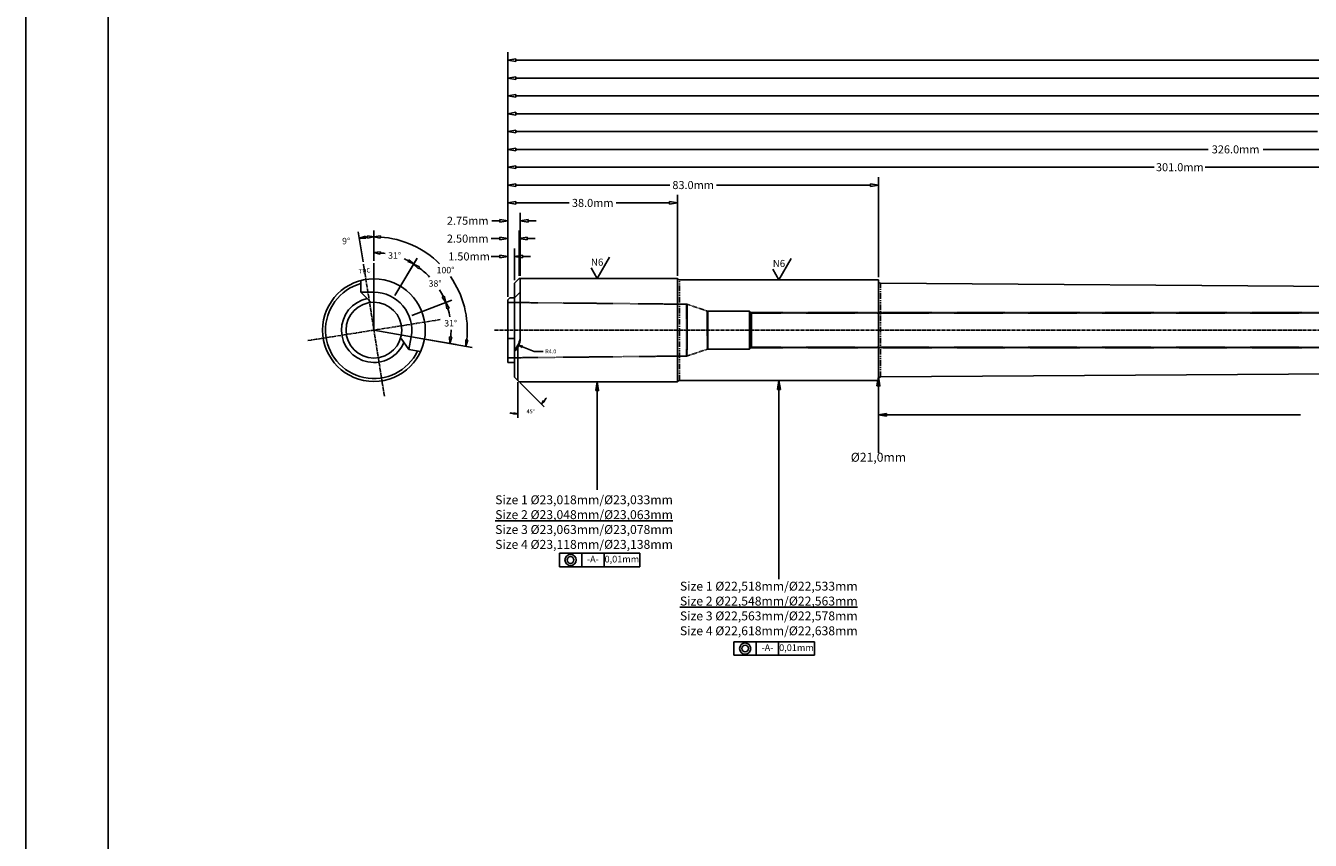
# Model space of a CAD drawing. Units: inches. Extents: x 0 to 841, y 0 to 594.
# Drawn here: x 0 to 288, y 183 to 365 of the extents above; entities that cross this region are included whole.
import ezdxf
from ezdxf.enums import TextEntityAlignment as Align

# ---------------------------------------------------------------- set-up
doc = ezdxf.new("R2010")
doc.units = ezdxf.units.IN
doc.header["$MEASUREMENT"] = 0
for name, pattern in [('CENTER2', [1.125, 0.75, -0.125, 0.125, -0.125]), ('HIDDEN2', [0.1875, 0.125, -0.0625]), ('PHANTOM', [2.5, 1.25, -0.25, 0.25, -0.25, 0.25, -0.25])]:
    doc.linetypes.add(name, pattern=pattern)
for name, color, linetype in [('CENTER', 1, 'CENTER2'), ('CENTERLINE', 1, 'CENTER2'), ('HIDDEN', 5, 'HIDDEN2'), ('PHANTOM', 252, 'PHANTOM'), ('TEXT', 5, 'Continuous')]:
    doc.layers.add(name, color=color, linetype=linetype)
doc.dimstyles.get("Standard").update_dxf_attribs({"dimtxt": 0.18, "dimasz": 0.18, "dimexe": 0.18, "dimexo": 0.0625, "dimgap": 0.09, "dimtad": 0, "dimtih": 1, "dimtoh": 1, "dimdec": 4, "dimzin": 0, "dimdsep": 46, "dimtxsty": 'Standard', "dimcen": 0.09, "dimadec": 0, "dimazin": 0, "dimtfac": 1, "dimtdec": 4, "dimtofl": 0, "dimtmove": 0, "dimatfit": 3, "dimfxl": 0, "dimtolj": 1, "dimtzin": 0, "dimarcsym": 0})
doc.dimstyles.new('Standard$0', dxfattribs={"dimscale": 10, "dimtxt": 0.18, "dimasz": 0.18, "dimexe": 0.18, "dimexo": 0.0625, "dimgap": 0.09, "dimtad": 0, "dimtih": 1, "dimtoh": 1, "dimdec": 4, "dimzin": 4, "dimdsep": 46, "dimtxsty": 'Standard', "dimblk": 'CLOSEDBLANK', "dimcen": 0.09, "dimadec": 5, "dimazin": 1, "dimtfac": 1, "dimtdec": 4, "dimtofl": 0, "dimtmove": 0, "dimatfit": 3, "dimldrblk": 'CLOSEDBLANK', "dimfxl": 0, "dimtolj": 1, "dimtzin": 0, "dimarcsym": 0})

# ---------------------------------------------------------------- blocks, each defined once
blk = doc.blocks.new('_ClosedBlank')
at = {"color": 0, "linetype": 'ByBlock', "lineweight": -2}
for p, q in [((-1, 0.17), (0, 0)), ((-1, 0.17), (-1, -0.17)), ((0, 0), (-1, -0.17))]:
    blk.add_line(p, q, dxfattribs=at)
blk = doc.blocks.new('*D17')
at = {"color": 0, "lineweight": -2}
for p, q in [((108, 304.44), (108, 315.32)), ((109.5, 308.19), (109.5, 315.32)), ((106.2, 313.52), (104.25, 313.52)), ((111.3, 313.52), (113.1, 313.52))]:
    blk.add_line(p, q, dxfattribs=at)
at = {"layer": 'Defpoints', "color": 0}
for p in [(109.5, 313.52), (109.5, 307.56), (108, 303.81)]:
    blk.add_point(p, dxfattribs=at)
at = {"color": 0, "lineweight": -2, "xscale": 1.8, "yscale": 1.8, "zscale": 1.8}
blk.add_blockref('_ClosedBlank', (108, 313.52), dxfattribs=at)
at = {"color": 0, "lineweight": -2, "xscale": 1.8, "yscale": 1.8, "zscale": 1.8, "rotation": 180}
blk.add_blockref('_ClosedBlank', (109.5, 313.52), dxfattribs=at)
at = {"color": 0, "insert": (99.3, 313.52), "char_height": 1.8, "attachment_point": 5}
blk.add_mtext('\\A1;1.50mm', dxfattribs=at)
blk = doc.blocks.new('*D18')
at = {"color": 0, "lineweight": -2}
for p, q in [((108, 304.44), (108, 327.32)), ((109.8, 325.52), (121.75, 325.52)), ((144.2, 325.52), (132.25, 325.52)), ((146, 309.19), (146, 327.32))]:
    blk.add_line(p, q, dxfattribs=at)
at = {"layer": 'Defpoints', "color": 0}
for p in [(146, 325.52), (146, 308.56), (108, 303.81)]:
    blk.add_point(p, dxfattribs=at)
at = {"color": 0, "lineweight": -2, "xscale": 1.8, "yscale": 1.8, "zscale": 1.8, "rotation": 180}
blk.add_blockref('_ClosedBlank', (108, 325.52), dxfattribs=at)
at = {"color": 0, "lineweight": -2, "xscale": 1.8, "yscale": 1.8, "zscale": 1.8}
blk.add_blockref('_ClosedBlank', (146, 325.52), dxfattribs=at)
at = {"color": 0, "insert": (127, 325.52), "char_height": 1.8, "attachment_point": 5}
blk.add_mtext('\\A1;38.0mm', dxfattribs=at)
blk = doc.blocks.new('*D19')
at = {"color": 0, "lineweight": -2}
for p, q in [((108, 304.44), (108, 331.32)), ((191, 308.9), (191, 331.32)), ((109.8, 329.52), (144.25, 329.52)), ((189.2, 329.52), (154.75, 329.52))]:
    blk.add_line(p, q, dxfattribs=at)
at = {"layer": 'Defpoints', "color": 0}
for p in [(108, 329.52), (191, 308.27), (108, 303.81)]:
    blk.add_point(p, dxfattribs=at)
at = {"color": 0, "lineweight": -2, "xscale": 1.8, "yscale": 1.8, "zscale": 1.8, "rotation": 180}
blk.add_blockref('_ClosedBlank', (108, 329.52), dxfattribs=at)
at = {"color": 0, "lineweight": -2, "xscale": 1.8, "yscale": 1.8, "zscale": 1.8}
blk.add_blockref('_ClosedBlank', (191, 329.52), dxfattribs=at)
at = {"color": 0, "insert": (149.5, 329.52), "char_height": 1.8, "attachment_point": 5}
blk.add_mtext('\\A1;83.0mm', dxfattribs=at)
blk = doc.blocks.new('*D20')
at = {"color": 0, "lineweight": -2}
for p, q in [((108, 304.44), (108, 335.32)), ((409, 306.62), (409, 335.32)), ((109.8, 333.52), (252.8, 333.52)), ((407.2, 333.52), (264.2, 333.52))]:
    blk.add_line(p, q, dxfattribs=at)
at = {"layer": 'Defpoints', "color": 0}
for p in [(108, 333.52), (409, 306), (108, 303.81)]:
    blk.add_point(p, dxfattribs=at)
at = {"color": 0, "lineweight": -2, "xscale": 1.8, "yscale": 1.8, "zscale": 1.8, "rotation": 180}
blk.add_blockref('_ClosedBlank', (108, 333.52), dxfattribs=at)
at = {"color": 0, "lineweight": -2, "xscale": 1.8, "yscale": 1.8, "zscale": 1.8}
blk.add_blockref('_ClosedBlank', (409, 333.52), dxfattribs=at)
at = {"color": 0, "insert": (258.5, 333.52), "char_height": 1.8, "attachment_point": 5}
blk.add_mtext('\\A1;301.0mm', dxfattribs=at)
blk = doc.blocks.new('*D21')
at = {"color": 0, "lineweight": -2}
for p, q in [((108, 304.44), (108, 339.32)), ((109.8, 337.52), (264.85, 337.52)), ((432.2, 337.52), (277.15, 337.52)), ((434, 306.11), (434, 339.32))]:
    blk.add_line(p, q, dxfattribs=at)
at = {"layer": 'Defpoints', "color": 0}
for p in [(108, 337.52), (434, 305.49), (108, 303.81)]:
    blk.add_point(p, dxfattribs=at)
at = {"color": 0, "lineweight": -2, "xscale": 1.8, "yscale": 1.8, "zscale": 1.8, "rotation": 180}
blk.add_blockref('_ClosedBlank', (108, 337.52), dxfattribs=at)
at = {"color": 0, "lineweight": -2, "xscale": 1.8, "yscale": 1.8, "zscale": 1.8}
blk.add_blockref('_ClosedBlank', (434, 337.52), dxfattribs=at)
at = {"color": 0, "insert": (271, 337.52), "char_height": 1.8, "attachment_point": 5}
blk.add_mtext('\\A1;326.0mm', dxfattribs=at)
blk = doc.blocks.new('*D22')
at = {"color": 0, "lineweight": -2}
for p, q in [((108, 304.44), (108, 343.32)), ((483, 306.02), (483, 343.32)), ((109.8, 341.52), (289.35, 341.52)), ((481.2, 341.52), (301.65, 341.52))]:
    blk.add_line(p, q, dxfattribs=at)
at = {"layer": 'Defpoints', "color": 0}
for p in [(483, 341.52), (483, 305.4), (108, 303.81)]:
    blk.add_point(p, dxfattribs=at)
at = {"color": 0, "lineweight": -2, "xscale": 1.8, "yscale": 1.8, "zscale": 1.8, "rotation": 180}
blk.add_blockref('_ClosedBlank', (108, 341.52), dxfattribs=at)
at = {"color": 0, "lineweight": -2, "xscale": 1.8, "yscale": 1.8, "zscale": 1.8}
blk.add_blockref('_ClosedBlank', (483, 341.52), dxfattribs=at)
at = {"color": 0, "insert": (295.5, 341.52), "char_height": 1.8, "attachment_point": 5}
blk.add_mtext('\\A1;375.0mm', dxfattribs=at)
blk = doc.blocks.new('*D23')
at = {"color": 0, "lineweight": -2}
for p, q in [((108, 304.44), (108, 347.32)), ((109.8, 345.52), (309.15, 345.52)), ((520.2, 345.52), (320.85, 345.52)), ((522, 305.4), (522, 347.32))]:
    blk.add_line(p, q, dxfattribs=at)
at = {"layer": 'Defpoints', "color": 0}
for p in [(522, 345.52), (108, 303.81), (522, 304.77)]:
    blk.add_point(p, dxfattribs=at)
at = {"color": 0, "lineweight": -2, "xscale": 1.8, "yscale": 1.8, "zscale": 1.8, "rotation": 180}
blk.add_blockref('_ClosedBlank', (108, 345.52), dxfattribs=at)
at = {"color": 0, "lineweight": -2, "xscale": 1.8, "yscale": 1.8, "zscale": 1.8}
blk.add_blockref('_ClosedBlank', (522, 345.52), dxfattribs=at)
at = {"color": 0, "insert": (315, 345.52), "char_height": 1.8, "attachment_point": 5}
blk.add_mtext('\\A1;414.0mm', dxfattribs=at)
blk = doc.blocks.new('*D24')
at = {"color": 0, "lineweight": -2}
for p, q in [((108, 304.44), (108, 351.31)), ((656, 305.25), (656, 351.31)), ((109.8, 349.51), (375.85, 349.51)), ((654.2, 349.51), (388.15, 349.51))]:
    blk.add_line(p, q, dxfattribs=at)
at = {"layer": 'Defpoints', "color": 0}
for p in [(656, 349.51), (108, 303.81), (656, 304.62)]:
    blk.add_point(p, dxfattribs=at)
at = {"color": 0, "lineweight": -2, "xscale": 1.8, "yscale": 1.8, "zscale": 1.8, "rotation": 180}
blk.add_blockref('_ClosedBlank', (108, 349.51), dxfattribs=at)
at = {"color": 0, "lineweight": -2, "xscale": 1.8, "yscale": 1.8, "zscale": 1.8}
blk.add_blockref('_ClosedBlank', (656, 349.51), dxfattribs=at)
at = {"color": 0, "insert": (382, 349.51), "char_height": 1.8, "attachment_point": 5}
blk.add_mtext('\\A1;548.0mm', dxfattribs=at)
blk = doc.blocks.new('*D25')
at = {"color": 0, "lineweight": -2}
for p, q in [((108, 304.44), (108, 355.31)), ((692, 305), (692, 355.31)), ((109.8, 353.51), (393.85, 353.51)), ((690.2, 353.51), (406.15, 353.51))]:
    blk.add_line(p, q, dxfattribs=at)
at = {"layer": 'Defpoints', "color": 0}
for p in [(692, 353.51), (108, 303.81), (692, 304.37)]:
    blk.add_point(p, dxfattribs=at)
at = {"color": 0, "lineweight": -2, "xscale": 1.8, "yscale": 1.8, "zscale": 1.8, "rotation": 180}
blk.add_blockref('_ClosedBlank', (108, 353.51), dxfattribs=at)
at = {"color": 0, "lineweight": -2, "xscale": 1.8, "yscale": 1.8, "zscale": 1.8}
blk.add_blockref('_ClosedBlank', (692, 353.51), dxfattribs=at)
at = {"color": 0, "insert": (400, 353.51), "char_height": 1.8, "attachment_point": 5}
blk.add_mtext('\\A1;584.0mm', dxfattribs=at)
blk = doc.blocks.new('*D26')
at = {"color": 0, "lineweight": -2}
for p, q in [((106.2, 317.52), (104.25, 317.52)), ((108, 304.44), (108, 319.32)), ((110.5, 309.19), (110.5, 319.32)), ((112.3, 317.52), (114.1, 317.52))]:
    blk.add_line(p, q, dxfattribs=at)
at = {"layer": 'Defpoints', "color": 0}
for p in [(110.5, 317.52), (110.5, 308.56), (108, 303.81)]:
    blk.add_point(p, dxfattribs=at)
at = {"color": 0, "lineweight": -2, "xscale": 1.8, "yscale": 1.8, "zscale": 1.8}
blk.add_blockref('_ClosedBlank', (108, 317.52), dxfattribs=at)
at = {"color": 0, "lineweight": -2, "xscale": 1.8, "yscale": 1.8, "zscale": 1.8, "rotation": 180}
blk.add_blockref('_ClosedBlank', (110.5, 317.52), dxfattribs=at)
at = {"color": 0, "insert": (99, 317.52), "char_height": 1.8, "attachment_point": 5}
blk.add_mtext('\\A1;2.50mm', dxfattribs=at)
blk = doc.blocks.new('*D27')
at = {"color": 0, "lineweight": -2}
for p, q in [((108, 308.87), (108, 323.32)), ((110.75, 309.19), (110.75, 323.32)), ((106.2, 321.52), (104.4, 321.52)), ((112.55, 321.52), (114.35, 321.52))]:
    blk.add_line(p, q, dxfattribs=at)
at = {"layer": 'Defpoints', "color": 0}
for p in [(110.75, 321.52), (108, 308.25), (110.75, 308.56)]:
    blk.add_point(p, dxfattribs=at)
at = {"color": 0, "lineweight": -2, "xscale": 1.8, "yscale": 1.8, "zscale": 1.8}
blk.add_blockref('_ClosedBlank', (108, 321.52), dxfattribs=at)
at = {"color": 0, "lineweight": -2, "xscale": 1.8, "yscale": 1.8, "zscale": 1.8, "rotation": 180}
blk.add_blockref('_ClosedBlank', (110.75, 321.52), dxfattribs=at)
at = {"color": 0, "insert": (99, 321.52), "char_height": 1.8, "attachment_point": 5}
blk.add_mtext('\\A1;2.75mm', dxfattribs=at)
blk = doc.blocks.new('*D28')
at = {"color": 0, "lineweight": -2}
for p, q in [((108, 304.44), (108, 359.31)), ((109.8, 357.51), (414.35, 357.51)), ((731.2, 357.51), (426.65, 357.51)), ((733, 304.92), (733, 359.31))]:
    blk.add_line(p, q, dxfattribs=at)
at = {"layer": 'Defpoints', "color": 0}
for p in [(733, 357.51), (108, 303.81), (733, 304.3)]:
    blk.add_point(p, dxfattribs=at)
at = {"color": 0, "lineweight": -2, "xscale": 1.8, "yscale": 1.8, "zscale": 1.8, "rotation": 180}
blk.add_blockref('_ClosedBlank', (108, 357.51), dxfattribs=at)
at = {"color": 0, "lineweight": -2, "xscale": 1.8, "yscale": 1.8, "zscale": 1.8}
blk.add_blockref('_ClosedBlank', (733, 357.51), dxfattribs=at)
at = {"color": 0, "insert": (420.5, 357.51), "char_height": 1.8, "attachment_point": 5}
blk.add_mtext('\\A1;625.0mm', dxfattribs=at)
blk = doc.blocks.new('*D44')
at = {"color": 0, "lineweight": -2}
for p, q in [((110.25, 285.37), (110.25, 277.34)), ((110.72, 285.21), (116.16, 279.78))]:
    blk.add_line(p, q, dxfattribs=at)
for start, end in [(321.9261, 328.8523), (256.1477, 263.0739)]:
    blk.add_arc((110.25, 285.68), 7.45, start, end, dxfattribs=at)
at = {"layer": 'Defpoints', "color": 0}
for p in [(110.25, 293.73), (109.5, 286.44), (110.25, 285.68), (110.5, 285.43), (112.18, 278.49)]:
    blk.add_point(p, dxfattribs=at)
at = {"color": 0, "lineweight": -2, "xscale": 0.8999999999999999, "yscale": 0.8999999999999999, "zscale": 0.8999999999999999}
for p, rotation in [((115.52, 280.42), 228.4630740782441), ((110.25, 278.24), 356.5369259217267)]:
    blk.add_blockref('_ClosedBlank', p, dxfattribs=dict(at, rotation=rotation))
at = {"color": 0, "insert": (113.1, 278.8), "char_height": 0.9, "attachment_point": 5}
blk.add_mtext('\\A1;45°', dxfattribs=at)
blk = doc.blocks.new('*D15')
at = {"color": 0, "lineweight": -2}
for p, q in [((78, 312.5), (78, 315.81)), ((82.67, 304.77), (87.69, 313.12))]:
    blk.add_line(p, q, dxfattribs=at)
for start, end in [(81.7869, 85.2476), (63.7524, 66.9446)]:
    blk.add_arc((78, 297), 17.37, start, end, dxfattribs=at)
at = {"layer": 'Defpoints', "color": 0}
for p in [(78, 312), (84.13, 313.25), (82.41, 304.34), (78, 297), (78, 297)]:
    blk.add_point(p, dxfattribs=at)
at = {"color": 0, "lineweight": -2, "xscale": 1.44, "yscale": 1.44, "zscale": 1.44}
for p, rotation in [((78, 314.37), 177.6237779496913), ((86.94, 311.89), 331.3762212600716)]:
    blk.add_blockref('_ClosedBlank', p, dxfattribs=dict(at, rotation=rotation))
at = {"color": 0, "insert": (82.64, 313.73), "char_height": 1.44, "attachment_point": 5}
blk.add_mtext('\\A1;31°', dxfattribs=at)
blk = doc.blocks.new('*D16')
at = {"color": 0, "lineweight": -2}
for p, q in [((82.67, 304.77), (87.62, 313.01)), ((86.46, 300.25), (95.44, 303.69))]:
    blk.add_line(p, q, dxfattribs=at)
for start, end in [(43.6521, 54.2118), (25.7882, 31.5463)]:
    blk.add_arc((78, 297), 17.24, start, end, dxfattribs=at)
at = {"layer": 'Defpoints', "color": 0}
for p in [(89.9, 309.47), (82.41, 304.34), (86, 300.07), (78, 297), (78, 297)]:
    blk.add_point(p, dxfattribs=at)
at = {"color": 0, "lineweight": -2, "xscale": 1.44, "yscale": 1.44, "zscale": 1.44}
for p, rotation in [((86.88, 311.77), 146.6059045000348), ((94.09, 303.18), 293.3940946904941)]:
    blk.add_blockref('_ClosedBlank', p, dxfattribs=dict(at, rotation=rotation))
at = {"color": 0, "insert": (91.7, 307.46), "char_height": 1.44, "attachment_point": 5}
blk.add_mtext('\\A1;38°', dxfattribs=at)
blk = doc.blocks.new('*D40')
at = {"color": 0, "lineweight": -2}
for p, q in [((78, 312.5), (78, 319.36)), ((89.82, 294.92), (100.02, 293.12))]:
    blk.add_line(p, q, dxfattribs=at)
for start, end in [(45.3657, 86.0562), (353.9438, 35.0275)]:
    blk.add_arc((78, 297), 20.92, start, end, dxfattribs=at)
at = {"layer": 'Defpoints', "color": 0}
for p in [(78, 312), (97.21, 305.29), (78, 297), (78, 297), (89.33, 295)]:
    blk.add_point(p, dxfattribs=at)
at = {"color": 0, "lineweight": -2, "xscale": 1.44, "yscale": 1.44, "zscale": 1.44}
for p, rotation in [((78, 317.92), 178.028112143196), ((98.61, 293.37), 261.971886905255)]:
    blk.add_blockref('_ClosedBlank', p, dxfattribs=dict(at, rotation=rotation))
at = {"color": 0, "insert": (94.03, 310.45), "char_height": 1.44, "attachment_point": 5}
blk.add_mtext('\\A1;100°', dxfattribs=at)
blk = doc.blocks.new('*D41')
at = {"color": 0, "lineweight": -2}
for p, q in [((86.46, 300.25), (95.47, 303.71)), ((89.82, 294.92), (96.43, 293.75))]:
    blk.add_line(p, q, dxfattribs=at)
for start, end in [(9.9283, 16.2222), (354.7778, 0.3259)]:
    blk.add_arc((78, 297), 17.27, start, end, dxfattribs=at)
at = {"layer": 'Defpoints', "color": 0}
for p in [(86, 300.07), (94.98, 300.2), (78, 297), (78, 297), (89.33, 295)]:
    blk.add_point(p, dxfattribs=at)
at = {"color": 0, "lineweight": -2, "xscale": 1.44, "yscale": 1.44, "zscale": 1.44}
for p, rotation in [((94.13, 303.19), 108.6110943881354), ((95.01, 294), 262.3889047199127)]:
    blk.add_blockref('_ClosedBlank', p, dxfattribs=dict(at, rotation=rotation))
at = {"color": 0, "insert": (95.2, 298.54), "char_height": 1.44, "attachment_point": 5}
blk.add_mtext('\\A1;31°', dxfattribs=at)
blk = doc.blocks.new('*D42')
at = {"color": 0, "lineweight": -2}
for p, q in [((75.58, 312.31), (74.5, 319.07)), ((78, 312.5), (78, 319.35))]:
    blk.add_line(p, q, dxfattribs=at)
blk.add_arc((78, 297), 20.91, 93.9466, 95.0534, dxfattribs=at)
at = {"layer": 'Defpoints', "color": 0}
for p in [(76.91, 317.88), (75.65, 311.82), (78, 312), (78, 297), (80.35, 282.18)]:
    blk.add_point(p, dxfattribs=at)
at = {"color": 0, "lineweight": -2, "xscale": 1.44, "yscale": 1.44, "zscale": 1.44}
for p, rotation in [((74.73, 317.65), 187.0267074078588), ((78, 317.91), 1.973292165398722)]:
    blk.add_blockref('_ClosedBlank', p, dxfattribs=dict(at, rotation=rotation))
at = {"color": 0, "insert": (71.78, 316.96), "char_height": 1.44, "attachment_point": 5}
blk.add_mtext('\\A1;9°', dxfattribs=at)
blk = doc.blocks.new('*D43')
at = {"color": 0, "lineweight": -2}
for p, q in [((113.86, 292.23), (111.29, 293.27)), ((115.89, 292.23), (113.86, 292.23))]:
    blk.add_line(p, q, dxfattribs=at)
at = {"layer": 'Defpoints', "color": 0}
for p in [(106.75, 295.11), (110.46, 293.61)]:
    blk.add_point(p, dxfattribs=at)
at = {"color": 0, "lineweight": -2, "xscale": 0.8999999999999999, "yscale": 0.8999999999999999, "zscale": 0.8999999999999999, "rotation": 157.9266221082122}
blk.add_blockref('_ClosedBlank', (110.46, 293.61), dxfattribs=at)
at = {"color": 0, "insert": (117.61, 292.23), "char_height": 0.9, "attachment_point": 5}
blk.add_mtext('\\A1;R4.0', dxfattribs=at)

msp = doc.modelspace()

# ---------------------------------------------------------------- linework, layer by layer
at = {"color": 1}
for q in [(77.99996, 312), (92.77208, 294.39527)]:
    msp.add_line((77.99996, 297), q, dxfattribs=at)
for p, q in [((126.62682, 310.94625), (128.00164, 308.565)), ((128.00164, 308.565), (130.75127, 313.3275)), ((168.72684, 308.275), (171.47648, 313.0375)), ((75.09521, 305.4824), (75.09521, 308.1271)), ((109.49996, 307.56164), (110.50332, 308.565)), ((110.50332, 308.565), (145.99996, 308.565)), ((110.74996, 295.11191), (110.74996, 308.565)), ((145.99996, 285.435), (145.99996, 308.565)), ((146.45373, 308.275), (190.99996, 308.275)), ((167.35203, 310.65625), (168.72684, 308.275)), ((190.99996, 285.725), (190.99996, 308.275)), ((77.21026, 303.36735), (75.09521, 305.4824)), ((77.99996, 305.4824), (75.09521, 305.4824)), ((109.49996, 304.25), (109.49996, 307.56164)), ((109.49996, 304.2324), (110.74996, 305.4824)), ((191.49652, 307.49658), (408.99996, 306)), ((77.21026, 303.36735), (77.19545, 303.198)), ((107.99996, 303.815), (108.43496, 304.25)), ((107.99996, 289.75), (107.99996, 303.815)), ((107.99996, 303.20498), (109.49996, 303.19002)), ((108.43496, 304.25), (109.49996, 304.25)), ((109.49996, 294.66584), (109.49996, 304.86363)), ((83.9641, 295.13143), (84.13345, 295.11661)), ((84.13345, 295.11661), (85.84909, 292.66642)), ((85.84909, 292.66642), (86.3535, 295.52704)), ((107.99996, 295.12402), (109.49996, 295.12402)), ((109.24996, 295.12402), (109.49996, 295.12402)), ((109.49996, 286.43835), (109.49996, 294.66584)), ((110.25332, 293.72903), (110.25332, 285.685)), ((85.84909, 292.66642), (88.45362, 292.20717)), ((107.99996, 289.75), (109.49996, 289.75)), ((191.49996, 286.50344), (408.99996, 288)), ((109.49996, 286.43835), (110.50332, 285.435)), ((110.50332, 285.435), (145.99996, 285.435)), ((146.45373, 285.725), (190.99332, 285.725)), ((190.99996, 278), (285.57106, 278)), ((119.54128, 243.96997), (119.54128, 246.96997))]:
    msp.add_line(p, q)
for points in [[(-0.00004, 0), (840.99996, 0), (840.99996, 594), (-0.00004, 594)], [(18.49996, 20), (822.49996, 20), (822.49996, 574), (18.49996, 574)]]:
    msp.add_lwpolyline(points, close=True)
for radius in [11.5, 6.25]:
    msp.add_circle((77.99996, 297), radius)
for centre, radius, start, end in [((146.45373, 308.775), 0.5, 204.8345875, 270), ((191.49996, 307.99657), 0.5, 180, 270), ((77.99996, 297), 10.85, 105.5285723, 334.4714272), ((77.99996, 297), 8.4824, 349.9999996, 89.9999999), ((77.99996, 297), 7.25, 102.0437004, 337.9562974), ((106.74996, 295.57116), 4, 313.4325366, 0), ((106.74996, 295.11191), 4, 313.4325366, 0), ((146.45373, 285.225), 0.5, 90, 155.1654125), ((191.49996, 286.00342), 0.5, 90, 180)]:
    msp.add_arc(centre, radius, start, end)
at = {"layer": 'CENTER'}
msp.add_line((80.34648, 282.18467), (75.65345, 311.81532), dxfattribs=at)
at = {"layer": 'CENTERLINE'}
for p, q in [((92.81529, 299.34651), (63.18464, 294.65348)), ((104.99996, 297), (735.99996, 297))]:
    msp.add_line(p, q, dxfattribs=at)
at = {"layer": 'HIDDEN'}
for p, q in [((109.49996, 303.19002), (148.02475, 302.80578)), ((148.02466, 291.19421), (148.02466, 302.80578)), ((148.17841, 291.22005), (148.17841, 302.77997)), ((148.17841, 302.77997), (152.62634, 301.29088)), ((152.62634, 292.70913), (152.62634, 301.29088)), ((152.78507, 292.735), (152.78507, 301.265)), ((152.78514, 301.265), (162.12332, 301.265)), ((162.12332, 292.735), (162.12332, 301.265)), ((162.12332, 301.265), (162.57832, 300.81)), ((162.42592, 300.9624), (732.99996, 300.9624)), ((162.42592, 293.0376), (162.42592, 300.9624)), ((162.57832, 300.81), (732.99996, 300.81)), ((162.57832, 293.19), (162.57832, 300.81)), ((107.99996, 290.79501), (148.02466, 291.19421)), ((148.17841, 291.22005), (152.62634, 292.70913)), ((152.78507, 292.735), (162.12332, 292.735)), ((162.12332, 292.735), (162.61335, 293.22503)), ((162.42592, 293.0376), (732.99996, 293.0376)), ((162.57832, 293.19), (732.99996, 293.19))]:
    msp.add_line(p, q, dxfattribs=at)
for centre, start, end in [((148.01977, 302.3058), 71.5017102, 89.428565), ((152.78514, 301.765), 251.4904, 270), ((148.01967, 291.69419), 270.571435, 288.50951), ((152.78507, 292.235), 90, 108.50951)]:
    msp.add_arc(centre, 0.5, start, end, dxfattribs=at)
at = {"layer": 'PHANTOM'}
for p, q in [((146.45373, 285.725), (146.45373, 308.275)), ((191.49996, 286.50342), (191.49996, 307.49657))]:
    msp.add_line(p, q, dxfattribs=at)
at = {"layer": 'TEXT', "color": 7}
for p, q in [((119.54128, 246.96997), (124.54128, 246.96997)), ((124.54128, 246.96997), (129.54128, 246.96997)), ((124.54128, 243.96997), (124.54128, 246.96997)), ((129.54128, 246.96997), (137.54128, 246.96997)), ((129.54128, 243.96997), (129.54128, 246.96997)), ((137.54128, 243.96997), (137.54128, 246.96997)), ((119.54128, 243.96997), (124.54128, 243.96997)), ((124.54128, 243.96997), (129.54128, 243.96997)), ((129.54128, 243.96997), (137.54128, 243.96997)), ((158.6478, 224.11717), (158.6478, 227.11717)), ((158.6478, 227.11717), (163.6478, 227.11717)), ((163.6478, 227.11717), (168.6478, 227.11717)), ((163.6478, 224.11717), (163.6478, 227.11717)), ((168.6478, 227.11717), (176.6478, 227.11717)), ((168.6478, 224.11717), (168.6478, 227.11717)), ((176.6478, 224.11717), (176.6478, 227.11717)), ((158.6478, 224.11717), (163.6478, 224.11717)), ((163.6478, 224.11717), (168.6478, 224.11717)), ((168.6478, 224.11717), (176.6478, 224.11717))]:
    msp.add_line(p, q, dxfattribs=at)
for centre, radius in [((122.04128, 245.46997), 1.25), ((122.04128, 245.46997), 0.75), ((161.1478, 225.61717), 1.25), ((161.1478, 225.61717), 0.75)]:
    msp.add_circle(centre, radius, dxfattribs=at)

# ---------------------------------------------------------------- block references
at = {"xscale": -1.799999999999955, "yscale": 1.800000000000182, "zscale": 1.8}
msp.add_blockref('_ClosedBlank', (190.99996, 278), dxfattribs=at)

# ---------------------------------------------------------------- texts
for p in [(128.00164, 310.94625), (168.72684, 310.65625)]:
    msp.add_text('N6', height=1.5875).set_placement(p, align=Align.BOTTOM_CENTER)
at = {"insert": (75.91953, 310.13533), "char_height": 1, "width": 2.2352304, "attachment_point": 5, "rotation": 9}
msp.add_mtext('TDC', dxfattribs=at)
at = {"insert": (190.99996, 269.5), "char_height": 2, "width": 10.5482646, "attachment_point": 2}
msp.add_mtext('\\A1;%%C21,0mm', dxfattribs=at)
at = {"layer": 'TEXT', "color": 7}
for s, insert, char_height, width, attachment_point in [('\\A1;Size 1 %%C23,018mm/%%C23,033mm\\P{\\LSize 2 %%C23,048mm/%%C23,063mm}\\PSize 3 %%C23,063mm/%%C23,078mm\\PSize 4 %%C23,118mm/%%C23,138mm', (105.15622, 259.96997), 2, 48.5376086, 1), ('-A-', (127.04128, 245.46997), 1.5, 1.19634, 5), ('0,01mm', (133.54128, 245.46997), 1.5, 6.6720954, 5), ('\\A1;Size 1 %%C22,518mm/%%C22,533mm\\P{\\LSize 2 %%C22,548mm/%%C22,563mm}\\PSize 3 %%C22,563mm/%%C22,578mm\\PSize 4 %%C22,618mm/%%C22,638mm', (146.53995, 240.60015), 2, 48.5376086, 1), ('-A-', (166.1478, 225.61717), 1.5, 1.19634, 5), ('0,01mm', (172.6478, 225.61717), 1.5, 6.6720954, 5)]:
    msp.add_mtext(s, dxfattribs=dict(at, insert=insert, char_height=char_height, width=width, attachment_point=attachment_point))

# ---------------------------------------------------------------- dimensions: what is measured, and where the dimension line sits
for base, p1, p2, picture, middle in [((732.99996, 357.51176), (107.99996, 303.815), (732.99996, 304.3), '*D28', (420.49996, 357.51176)), ((691.99996, 353.51323), (107.99996, 303.815), (691.99996, 304.375), '*D25', (399.99996, 353.51323)), ((655.99996, 349.51469), (107.99996, 303.815), (655.99996, 304.625), '*D24', (381.99996, 349.51469)), ((521.99996, 345.51615), (107.99996, 303.815), (521.99996, 304.775), '*D23', (314.99996, 345.51615)), ((482.99996, 341.51761), (107.99996, 303.815), (482.99996, 305.4), '*D22', (295.49996, 341.51761)), ((107.99996, 337.51907), (433.99996, 305.49), (107.99996, 303.815), '*D21', (270.99996, 337.51907)), ((107.99996, 333.52053), (408.99996, 306), (107.99996, 303.815), '*D20', (258.49996, 333.52053)), ((107.99996, 329.51761), (190.99996, 308.275), (107.99996, 303.815), '*D19', (149.49996, 329.51761)), ((145.99996, 325.51761), (107.99996, 303.815), (145.99996, 308.565), '*D18', (126.99996, 325.51761))]:
    dim = msp.add_linear_dim(base=base, p1=p1, p2=p2, dimstyle='Standard$0', override={"dimscale": 10, "dimdec": 1, "dimpost": 'mm', "dimblk1": 'ClosedBlank', "dimblk2": 'ClosedBlank', "dimsah": 1})
    dim.commit()
    dim.dimension.update_dxf_attribs({"geometry": picture, "text_midpoint": middle})
for base, p1, p2, picture, middle in [((110.74996, 321.51761), (107.99996, 308.25), (110.74996, 308.565), '*D27', (98.99996, 321.51761)), ((110.50332, 317.51761), (107.99996, 303.815), (110.50332, 308.565), '*D26', (98.99996, 317.51761)), ((109.49996, 313.51761), (107.99996, 303.815), (109.49996, 307.56164), '*D17', (99.29996, 313.51761))]:
    dim = msp.add_linear_dim(base=base, p1=p1, p2=p2, dimstyle='Standard$0', override={"dimscale": 10, "dimdec": 2, "dimpost": 'mm', "dimblk1": 'ClosedBlank', "dimblk2": 'ClosedBlank', "dimsah": 1})
    dim.commit()
    dim.dimension.update_dxf_attribs({"geometry": picture, "text_midpoint": middle, "dimtype": 160})
for base, line1, line2, picture, middle in [((76.90563, 317.88112), ((77.99996, 297), (77.99996, 312)), ((80.34648, 282.18467), (75.65345, 311.81532)), '*D42', (71.77642, 316.96212)), ((89.90086, 309.46809), ((77.99996, 297), (82.41128, 304.34166)), ((77.99996, 297), (85.99611, 300.06943)), '*D16', (91.70108, 307.45772)), ((94.97506, 300.19724), ((77.99996, 297), (89.32525, 295.00304)), ((77.99996, 297), (85.99611, 300.06943)), '*D41', (95.2049, 298.53824))]:
    dim = msp.add_angular_dim_2l(base=base, line1=line1, line2=line2, dimstyle='Standard', override={"dimscale": 8, "dimblk1": 'ClosedBlank', "dimblk2": 'ClosedBlank', "dimsah": 1})
    dim.commit()
    dim.dimension.update_dxf_attribs({"geometry": picture, "text_midpoint": middle, "dimtype": 162})
for base, line1, line2, override, picture, middle in [((97.21334, 305.28784), ((77.99996, 297), (89.32525, 295.00304)), ((77.99996, 297), (77.99996, 312)), {"dimscale": 8, "dimblk1": 'ClosedBlank', "dimblk2": 'ClosedBlank', "dimsah": 1}, '*D40', (94.0292, 310.45012)), ((84.12886, 313.24822), ((77.99996, 297), (82.41128, 304.34166)), ((77.99996, 297), (77.99996, 312)), {"dimscale": 8, "dimblk1": 'ClosedBlank', "dimblk2": 'ClosedBlank', "dimsah": 1}, '*D15', (82.64075, 313.73413)), ((112.18144, 278.48915), ((110.25332, 293.72903), (110.25332, 285.685)), ((109.49996, 286.43835), (110.50332, 285.435)), {"dimscale": 5, "dimblk1": 'ClosedBlank', "dimblk2": 'ClosedBlank', "dimsah": 1}, '*D44', (113.10419, 278.80239))]:
    dim = msp.add_angular_dim_2l(base=base, line1=line1, line2=line2, dimstyle='Standard', override=override)
    dim.commit()
    dim.dimension.update_dxf_attribs({"geometry": picture, "text_midpoint": middle})
dim = msp.add_radius_dim(center=(106.74996, 295.11191), mpoint=(110.45678, 293.60874), dimstyle='Standard', override={"dimscale": 5, "dimdec": 1, "dimblk2": 'ClosedBlank', "dimsah": 1, "dimcen": 0})
dim.commit()
dim.dimension.update_dxf_attribs({"geometry": '*D43', "text_midpoint": (117.61452, 292.22684), "dimtype": 164})

# ---------------------------------------------------------------- leaders
msp.add_leader([(190.99996, 286.5), (190.99996, 269.5)], dimstyle='Standard', override={"dimscale": 1, "dimasz": 2, "dimgap": 0.09, "dimtad": 0, "dimldrblk": 'ClosedBlank'})
for points in [[(128.00164, 285.435), (128.00164, 261.20898)], [(168.72352, 285.725), (168.72352, 241.20276)]]:
    msp.add_leader(points, dimstyle='Standard', override={"dimscale": 1, "dimasz": 2, "dimgap": 0.09, "dimtad": 0, "dimldrblk": 'ClosedBlank'}, dxfattribs=at)

doc.saveas('drawing.dxf')
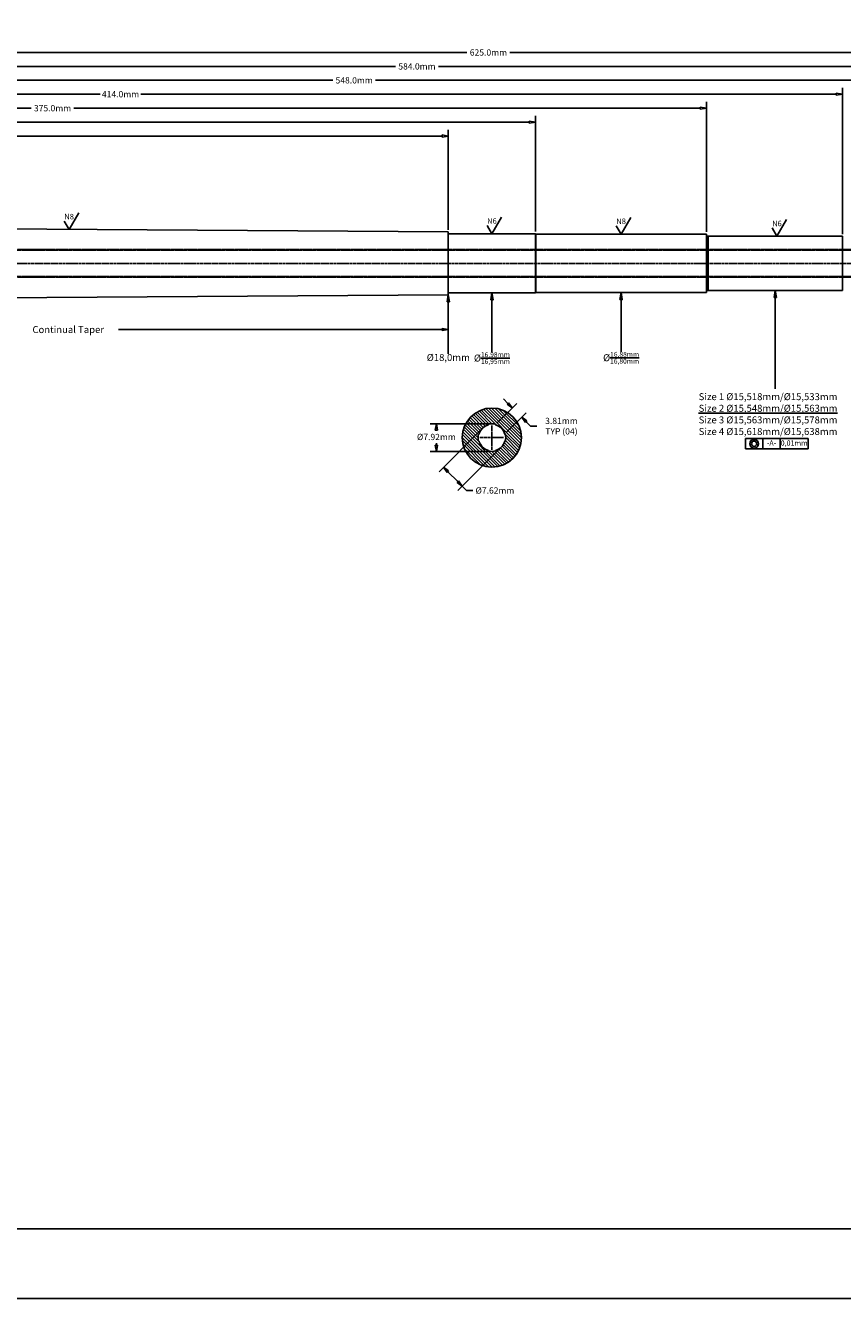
# Model space of a CAD drawing. Units: inches. Extents: x 0 to 841, y 0 to 594.
# Drawn here: x 288 to 522, y 0 to 365 of the extents above; entities that cross this region are included whole.
import ezdxf
from ezdxf.enums import TextEntityAlignment as Align

# ---------------------------------------------------------------- set-up
doc = ezdxf.new("R2010")
doc.units = ezdxf.units.IN
doc.header["$MEASUREMENT"] = 0
doc.linetypes.add('CENTER2', pattern=[1.125, 0.75, -0.125, 0.125, -0.125])
doc.linetypes.add('HIDDEN2', pattern=[0.1875, 0.125, -0.0625])
for name, color, linetype in [('CENTER', 1, 'CENTER2'), ('CENTERLINE', 1, 'CENTER2'), ('Hatch', 253, 'Continuous'), ('HIDDEN', 5, 'HIDDEN2'), ('TEXT', 5, 'Continuous')]:
    doc.layers.add(name, color=color, linetype=linetype)
doc.dimstyles.get("Standard").update_dxf_attribs({"dimtxt": 0.18, "dimasz": 0.18, "dimexe": 0.18, "dimexo": 0.0625, "dimgap": 0.09, "dimtad": 0, "dimtih": 1, "dimtoh": 1, "dimdec": 4, "dimzin": 0, "dimdsep": 46, "dimtxsty": 'Standard', "dimcen": 0.09, "dimadec": 0, "dimazin": 0, "dimtfac": 1, "dimtdec": 4, "dimtofl": 0, "dimtmove": 0, "dimatfit": 3, "dimfxl": 0, "dimtolj": 1, "dimtzin": 0, "dimarcsym": 0})
doc.dimstyles.new('Standard$0', dxfattribs={"dimscale": 10, "dimtxt": 0.18, "dimasz": 0.18, "dimexe": 0.18, "dimexo": 0.0625, "dimgap": 0.09, "dimtad": 0, "dimtih": 1, "dimtoh": 1, "dimdec": 4, "dimzin": 4, "dimdsep": 46, "dimtxsty": 'Standard', "dimblk": 'CLOSEDBLANK', "dimcen": 0.09, "dimadec": 5, "dimazin": 1, "dimtfac": 1, "dimtdec": 4, "dimtofl": 0, "dimtmove": 0, "dimatfit": 3, "dimldrblk": 'CLOSEDBLANK', "dimfxl": 0, "dimtolj": 1, "dimtzin": 0, "dimarcsym": 0})

# ---------------------------------------------------------------- blocks, each defined once
blk = doc.blocks.new('_ClosedBlank')
at = {"color": 0, "linetype": 'ByBlock', "lineweight": -2}
for p, q in [((-1, 0.17), (0, 0)), ((-1, 0.17), (-1, -0.17)), ((0, 0), (-1, -0.17))]:
    blk.add_line(p, q, dxfattribs=at)
blk = doc.blocks.new('*D20')
at = {"color": 0, "lineweight": -2}
for p, q in [((108, 304.44), (108, 335.32)), ((109.8, 333.52), (252.8, 333.52)), ((407.2, 333.52), (264.2, 333.52)), ((409, 306.62), (409, 335.32))]:
    blk.add_line(p, q, dxfattribs=at)
at = {"layer": 'Defpoints', "color": 0}
for p in [(108, 333.52), (108, 303.81), (409, 306)]:
    blk.add_point(p, dxfattribs=at)
at = {"color": 0, "lineweight": -2, "xscale": 1.8, "yscale": 1.8, "zscale": 1.8, "rotation": 180}
blk.add_blockref('_ClosedBlank', (108, 333.52), dxfattribs=at)
at = {"color": 0, "lineweight": -2, "xscale": 1.8, "yscale": 1.8, "zscale": 1.8}
blk.add_blockref('_ClosedBlank', (409, 333.52), dxfattribs=at)
at = {"color": 0, "insert": (258.5, 333.52), "char_height": 1.8, "attachment_point": 5}
blk.add_mtext('\\A1;301.0mm', dxfattribs=at)
blk = doc.blocks.new('*D21')
at = {"color": 0, "lineweight": -2}
for p, q in [((108, 304.44), (108, 339.32)), ((109.8, 337.52), (264.85, 337.52)), ((432.2, 337.52), (277.15, 337.52)), ((434, 306.11), (434, 339.32))]:
    blk.add_line(p, q, dxfattribs=at)
at = {"layer": 'Defpoints', "color": 0}
for p in [(108, 337.52), (108, 303.81), (434, 305.49)]:
    blk.add_point(p, dxfattribs=at)
at = {"color": 0, "lineweight": -2, "xscale": 1.8, "yscale": 1.8, "zscale": 1.8, "rotation": 180}
blk.add_blockref('_ClosedBlank', (108, 337.52), dxfattribs=at)
at = {"color": 0, "lineweight": -2, "xscale": 1.8, "yscale": 1.8, "zscale": 1.8}
blk.add_blockref('_ClosedBlank', (434, 337.52), dxfattribs=at)
at = {"color": 0, "insert": (271, 337.52), "char_height": 1.8, "attachment_point": 5}
blk.add_mtext('\\A1;326.0mm', dxfattribs=at)
blk = doc.blocks.new('*D22')
at = {"color": 0, "lineweight": -2}
for p, q in [((108, 304.44), (108, 343.32)), ((109.8, 341.52), (289.35, 341.52)), ((481.2, 341.52), (301.65, 341.52)), ((483, 306.02), (483, 343.32))]:
    blk.add_line(p, q, dxfattribs=at)
at = {"layer": 'Defpoints', "color": 0}
for p in [(483, 341.52), (108, 303.81), (483, 305.4)]:
    blk.add_point(p, dxfattribs=at)
at = {"color": 0, "lineweight": -2, "xscale": 1.8, "yscale": 1.8, "zscale": 1.8, "rotation": 180}
blk.add_blockref('_ClosedBlank', (108, 341.52), dxfattribs=at)
at = {"color": 0, "lineweight": -2, "xscale": 1.8, "yscale": 1.8, "zscale": 1.8}
blk.add_blockref('_ClosedBlank', (483, 341.52), dxfattribs=at)
at = {"color": 0, "insert": (295.5, 341.52), "char_height": 1.8, "attachment_point": 5}
blk.add_mtext('\\A1;375.0mm', dxfattribs=at)
blk = doc.blocks.new('*D23')
at = {"color": 0, "lineweight": -2}
for p, q in [((108, 304.44), (108, 347.32)), ((522, 305.4), (522, 347.32)), ((109.8, 345.52), (309.15, 345.52)), ((520.2, 345.52), (320.85, 345.52))]:
    blk.add_line(p, q, dxfattribs=at)
at = {"layer": 'Defpoints', "color": 0}
for p in [(522, 345.52), (108, 303.81), (522, 304.77)]:
    blk.add_point(p, dxfattribs=at)
at = {"color": 0, "lineweight": -2, "xscale": 1.8, "yscale": 1.8, "zscale": 1.8, "rotation": 180}
blk.add_blockref('_ClosedBlank', (108, 345.52), dxfattribs=at)
at = {"color": 0, "lineweight": -2, "xscale": 1.8, "yscale": 1.8, "zscale": 1.8}
blk.add_blockref('_ClosedBlank', (522, 345.52), dxfattribs=at)
at = {"color": 0, "insert": (315, 345.52), "char_height": 1.8, "attachment_point": 5}
blk.add_mtext('\\A1;414.0mm', dxfattribs=at)
blk = doc.blocks.new('*D24')
at = {"color": 0, "lineweight": -2}
for p, q in [((108, 304.44), (108, 351.31)), ((656, 305.25), (656, 351.31)), ((109.8, 349.51), (375.85, 349.51)), ((654.2, 349.51), (388.15, 349.51))]:
    blk.add_line(p, q, dxfattribs=at)
at = {"layer": 'Defpoints', "color": 0}
for p in [(656, 349.51), (108, 303.81), (656, 304.62)]:
    blk.add_point(p, dxfattribs=at)
at = {"color": 0, "lineweight": -2, "xscale": 1.8, "yscale": 1.8, "zscale": 1.8, "rotation": 180}
blk.add_blockref('_ClosedBlank', (108, 349.51), dxfattribs=at)
at = {"color": 0, "lineweight": -2, "xscale": 1.8, "yscale": 1.8, "zscale": 1.8}
blk.add_blockref('_ClosedBlank', (656, 349.51), dxfattribs=at)
at = {"color": 0, "insert": (382, 349.51), "char_height": 1.8, "attachment_point": 5}
blk.add_mtext('\\A1;548.0mm', dxfattribs=at)
blk = doc.blocks.new('*D25')
at = {"color": 0, "lineweight": -2}
for p, q in [((108, 304.44), (108, 355.31)), ((692, 305), (692, 355.31)), ((109.8, 353.51), (393.85, 353.51)), ((690.2, 353.51), (406.15, 353.51))]:
    blk.add_line(p, q, dxfattribs=at)
at = {"layer": 'Defpoints', "color": 0}
for p in [(692, 353.51), (108, 303.81), (692, 304.37)]:
    blk.add_point(p, dxfattribs=at)
at = {"color": 0, "lineweight": -2, "xscale": 1.8, "yscale": 1.8, "zscale": 1.8, "rotation": 180}
blk.add_blockref('_ClosedBlank', (108, 353.51), dxfattribs=at)
at = {"color": 0, "lineweight": -2, "xscale": 1.8, "yscale": 1.8, "zscale": 1.8}
blk.add_blockref('_ClosedBlank', (692, 353.51), dxfattribs=at)
at = {"color": 0, "insert": (400, 353.51), "char_height": 1.8, "attachment_point": 5}
blk.add_mtext('\\A1;584.0mm', dxfattribs=at)
blk = doc.blocks.new('*D28')
at = {"color": 0, "lineweight": -2}
for p, q in [((108, 304.44), (108, 359.31)), ((733, 304.92), (733, 359.31)), ((109.8, 357.51), (414.35, 357.51)), ((731.2, 357.51), (426.65, 357.51))]:
    blk.add_line(p, q, dxfattribs=at)
at = {"layer": 'Defpoints', "color": 0}
for p in [(733, 357.51), (108, 303.81), (733, 304.3)]:
    blk.add_point(p, dxfattribs=at)
at = {"color": 0, "lineweight": -2, "xscale": 1.8, "yscale": 1.8, "zscale": 1.8, "rotation": 180}
blk.add_blockref('_ClosedBlank', (108, 357.51), dxfattribs=at)
at = {"color": 0, "lineweight": -2, "xscale": 1.8, "yscale": 1.8, "zscale": 1.8}
blk.add_blockref('_ClosedBlank', (733, 357.51), dxfattribs=at)
at = {"color": 0, "insert": (420.5, 357.51), "char_height": 1.8, "attachment_point": 5}
blk.add_mtext('\\A1;625.0mm', dxfattribs=at)
blk = doc.blocks.new('*D37')
at = {"color": 0, "lineweight": -2}
for p, q in [((422.93, 251.12), (428.62, 256.81)), ((426.07, 256.81), (424.8, 258.09)), ((425.62, 248.43), (431.31, 254.12)), ((431.31, 251.57), (432.59, 250.3)), ((432.59, 250.3), (434.39, 250.3))]:
    blk.add_line(p, q, dxfattribs=at)
at = {"layer": 'Defpoints', "color": 0}
for p in [(427.35, 255.54), (422.49, 250.68), (425.18, 247.99)]:
    blk.add_point(p, dxfattribs=at)
at = {"color": 0, "lineweight": -2, "xscale": 1.8, "yscale": 1.8, "zscale": 1.8}
for p, rotation in [((427.35, 255.54), 315.0000000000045), ((430.04, 252.85), 135.0000000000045)]:
    blk.add_blockref('_ClosedBlank', p, dxfattribs=dict(at, rotation=rotation))
at = {"color": 0, "insert": (441.44, 250.3), "char_height": 1.8, "attachment_point": 5}
blk.add_mtext('\\A1;3.81mm\\PTYP (04)', dxfattribs=at)
blk = doc.blocks.new('*D38')
at = {"color": 0, "lineweight": -2}
for p, q in [((420.87, 250.96), (403.77, 250.96)), ((405.57, 249.16), (405.57, 248.99)), ((405.57, 244.84), (405.57, 245.39)), ((420.87, 243.04), (403.77, 243.04))]:
    blk.add_line(p, q, dxfattribs=at)
at = {"layer": 'Defpoints', "color": 0}
for p in [(405.57, 250.96), (421.5, 250.96), (421.5, 243.04)]:
    blk.add_point(p, dxfattribs=at)
at = {"color": 0, "lineweight": -2, "xscale": 1.8, "yscale": 1.8, "zscale": 1.8}
for p, rotation in [((405.57, 250.96), 90), ((405.57, 243.04), 270)]:
    blk.add_blockref('_ClosedBlank', p, dxfattribs=dict(at, rotation=rotation))
at = {"color": 0, "insert": (405.57, 247.19), "char_height": 1.8, "attachment_point": 5}
blk.add_mtext('\\A1;%%C7.92mm', dxfattribs=at)
blk = doc.blocks.new('*D39')
at = {"color": 0, "lineweight": -2}
for p, q in [((418.36, 249.25), (406.33, 237.21)), ((423.75, 243.86), (411.71, 231.83)), ((408.87, 237.21), (411.71, 234.37)), ((412.99, 233.1), (414.26, 231.83)), ((414.26, 231.83), (416.06, 231.83))]:
    blk.add_line(p, q, dxfattribs=at)
at = {"layer": 'Defpoints', "color": 0}
for p in [(418.81, 249.69), (424.19, 244.31), (407.6, 238.49)]:
    blk.add_point(p, dxfattribs=at)
at = {"color": 0, "lineweight": -2, "xscale": 1.8, "yscale": 1.8, "zscale": 1.8}
for p, rotation in [((407.6, 238.49), 135.0000000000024), ((412.99, 233.1), 315.0000000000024)]:
    blk.add_blockref('_ClosedBlank', p, dxfattribs=dict(at, rotation=rotation))
at = {"color": 0, "insert": (422.36, 231.83), "char_height": 1.8, "attachment_point": 5}
blk.add_mtext('\\A1;%%C7.62mm', dxfattribs=at)

msp = doc.modelspace()

# ---------------------------------------------------------------- hatches: boundary and pattern name
at = {"layer": 'Hatch'}
h = msp.add_hatch(dxfattribs=at)
h.set_pattern_fill('ANSI31', color=256, scale=5, angle=90, style=0)
h.set_pattern_definition([(135, (56, 246.99997), (-0.4419417, -0.4419417), [])])
h.paths.add_polyline_path([(413.00996, 247, 1), (429.98996, 247, 1)])
h.paths.add_polyline_path([(422.52489, 250.82506), (422.48606, 250.68017, -0.267949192), (425.18014, 247.9861), (425.32503, 248.02492, -0.131652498), (425.32503, 245.97507), (425.18014, 246.01389, -0.267949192), (422.48606, 243.31982), (422.52489, 243.17493, -0.131652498), (420.47504, 243.17493), (420.51386, 243.31982, -0.267949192), (417.81979, 246.01389), (417.6749, 245.97507, -0.131652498), (417.6749, 248.02492), (417.81979, 247.9861, -0.267949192), (420.51386, 250.68017), (420.47504, 250.82506, -0.131652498)], flags=16)

# ---------------------------------------------------------------- linework, layer by layer
for p, q in [((300.24824, 306.74829), (302.99787, 311.51079)), ((191.49652, 307.49658), (408.99996, 306)), ((298.87343, 309.12954), (300.24824, 306.74829)), ((420.12515, 307.87125), (421.49996, 305.49)), ((421.49996, 305.49), (424.24959, 310.2525)), ((457.1749, 307.78125), (458.54971, 305.4)), ((458.54971, 305.4), (461.29934, 310.1625)), ((501.87515, 307.15625), (503.24996, 304.775)), ((503.24996, 304.775), (505.99959, 309.5375)), ((408.99996, 288), (408.99996, 306)), ((408.99996, 305.49), (433.99996, 305.49)), ((433.99996, 288.51), (433.99996, 305.49)), ((434.09946, 305.4), (482.99996, 305.4)), ((434.09946, 288.6), (434.09946, 305.4)), ((482.99996, 288.6), (482.99996, 305.4)), ((483.49996, 304.775), (521.99996, 304.775)), ((483.49996, 289.225), (483.49996, 304.775)), ((521.99996, 289.225), (521.99996, 304.775)), ((434.09946, 288.6), (482.99996, 288.6)), ((483.49996, 289.225), (521.99996, 289.225)), ((191.49996, 286.50344), (408.99996, 288)), ((408.99996, 288.51), (433.99996, 288.51)), ((314.42887, 278), (408.99996, 278)), ((420.51386, 250.68017), (420.47504, 250.82506)), ((422.48606, 250.68017), (422.52489, 250.82506)), ((417.81979, 247.9861), (417.6749, 248.02492)), ((417.81979, 246.01389), (417.6749, 245.97507)), ((425.18014, 247.9861), (425.32503, 248.02492)), ((425.18014, 246.01389), (425.32503, 245.97507)), ((420.51386, 243.31982), (420.47504, 243.17493)), ((422.48606, 243.31982), (422.52489, 243.17493))]:
    msp.add_line(p, q)
for points in [[(-0.00004, 0), (840.99996, 0), (840.99996, 594), (-0.00004, 594)], [(18.49996, 20), (822.49996, 20), (822.49996, 574), (18.49996, 574)]]:
    msp.add_lwpolyline(points, close=True)
msp.add_circle((421.49996, 247), 8.49)
for centre, radius, start, end in [((434.09946, 305.5), 0.1, 185.7391705, 270), ((483.49996, 305.275), 0.5, 180, 270), ((522.09996, 304.725), 0.1, 180, 270), ((434.09946, 288.5), 0.1, 90, 174.2608295), ((483.49996, 288.725), 0.5, 90, 180), ((522.09996, 289.275), 0.1, 90, 180), ((421.49996, 247), 3.81, 105, 165), ((421.49996, 247), 3.96, 75, 105), ((421.49996, 247), 3.81, 15, 75), ((421.49996, 247), 3.96, 165, 195), ((421.49996, 247), 3.81, 195, 255), ((421.49996, 247), 3.81, 285, 345), ((421.49996, 247), 3.96, 345, 15), ((421.49996, 247), 3.96, 255, 285)]:
    msp.add_arc(centre, radius, start, end)
at = {"layer": 'CENTER'}
for p, q in [((421.49996, 243.535), (421.49996, 250.465)), ((418.03496, 247), (424.96496, 247))]:
    msp.add_line(p, q, dxfattribs=at)
at = {"layer": 'CENTERLINE'}
msp.add_line((104.99996, 297), (735.99996, 297), dxfattribs=at)
at = {"layer": 'HIDDEN'}
for p, q in [((162.42592, 300.9624), (732.99996, 300.9624)), ((162.57832, 300.81), (732.99996, 300.81)), ((162.42592, 293.0376), (732.99996, 293.0376)), ((162.57832, 293.19), (732.99996, 293.19))]:
    msp.add_line(p, q, dxfattribs=at)
at = {"layer": 'TEXT', "color": 7}
for p, q in [((494.18457, 243.74997), (494.18457, 246.74997)), ((494.18457, 246.74997), (499.18457, 246.74997)), ((499.18457, 246.74997), (504.18457, 246.74997)), ((499.18457, 243.74997), (499.18457, 246.74997)), ((504.18457, 246.74997), (512.18457, 246.74997)), ((504.18457, 243.74997), (504.18457, 246.74997)), ((512.18457, 243.74997), (512.18457, 246.74997)), ((494.18457, 243.74997), (499.18457, 243.74997)), ((499.18457, 243.74997), (504.18457, 243.74997)), ((504.18457, 243.74997), (512.18457, 243.74997))]:
    msp.add_line(p, q, dxfattribs=at)
for radius in [1.25, 0.75]:
    msp.add_circle((496.68457, 245.24997), radius, dxfattribs=at)

# ---------------------------------------------------------------- block references
at = {"xscale": 1.799999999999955, "yscale": 1.800000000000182, "zscale": 1.8}
msp.add_blockref('_ClosedBlank', (408.99996, 278), dxfattribs=at)

# ---------------------------------------------------------------- texts
for s, p in [('N8', (300.24824, 309.12954)), ('N6', (421.49996, 307.87125)), ('N8', (458.54971, 307.78125)), ('N6', (503.24996, 307.15625))]:
    msp.add_text(s, height=1.5875).set_placement(p, align=Align.BOTTOM_CENTER)
at = {"char_height": 2}
for s, insert, width, attachment_point in [('\\A1;Continual Taper', (299.99996, 278), 41.0979933, 5), ('\\A1;%%C18,0mm', (408.99996, 271), 10.5482646, 2), ('\\A1;%%C{\\H0.7x;\\S16,98mm/16,95mm;}', (421.49996, 271.51), 10.5482646, 2), ('\\A1;%%C{\\H0.7x;\\S16,88mm/16,80mm;}', (458.54971, 271.6), 10.5482646, 2)]:
    msp.add_mtext(s, dxfattribs=dict(at, insert=insert, width=width, attachment_point=attachment_point))
at = {"layer": 'TEXT', "color": 7}
for s, insert, char_height, width, attachment_point in [('\\A1;Size 1 %%C15,518mm/%%C15,533mm\\P{\\LSize 2 %%C15,548mm/%%C15,563mm}\\PSize 3 %%C15,563mm/%%C15,578mm\\PSize 4 %%C15,618mm/%%C15,638mm', (480.79315, 259.74997), 2, 48.5376086, 1), ('-A-', (501.68457, 245.24997), 1.5, 1.19634, 5), ('0,01mm', (508.18457, 245.24997), 1.5, 6.6720954, 5)]:
    msp.add_mtext(s, dxfattribs=dict(at, insert=insert, char_height=char_height, width=width, attachment_point=attachment_point))

# ---------------------------------------------------------------- dimensions: what is measured, and where the dimension line sits
for base, p1, p2, picture, middle in [((732.99996, 357.51176), (107.99996, 303.815), (732.99996, 304.3), '*D28', (420.49996, 357.51176)), ((691.99996, 353.51323), (107.99996, 303.815), (691.99996, 304.375), '*D25', (399.99996, 353.51323)), ((655.99996, 349.51469), (107.99996, 303.815), (655.99996, 304.625), '*D24', (381.99996, 349.51469)), ((521.99996, 345.51615), (107.99996, 303.815), (521.99996, 304.775), '*D23', (314.99996, 345.51615)), ((482.99996, 341.51761), (107.99996, 303.815), (482.99996, 305.4), '*D22', (295.49996, 341.51761)), ((107.99996, 337.51907), (433.99996, 305.49), (107.99996, 303.815), '*D21', (270.99996, 337.51907)), ((107.99996, 333.52053), (408.99996, 306), (107.99996, 303.815), '*D20', (258.49996, 333.52053))]:
    dim = msp.add_linear_dim(base=base, p1=p1, p2=p2, dimstyle='Standard$0', override={"dimscale": 10, "dimdec": 1, "dimpost": 'mm', "dimblk1": 'ClosedBlank', "dimblk2": 'ClosedBlank', "dimsah": 1})
    dim.commit()
    dim.dimension.update_dxf_attribs({"geometry": picture, "text_midpoint": middle})
dim = msp.add_linear_dim(base=(427.34633, 255.54044), p1=(425.18014, 247.9861), p2=(422.48606, 250.68017), angle=135, text='<>\\PTYP (04)', dimstyle='Standard$0', override={"dimdec": 2, "dimpost": 'mm'})
dim.commit()
dim.dimension.update_dxf_attribs({"geometry": '*D37', "text_midpoint": (441.43599, 250.30078), "dimtype": 160})
for base, p1, p2, angle, picture, middle in [((405.57225, 250.96), (421.49996, 243.04), (421.49996, 250.96), 90, '*D38', (405.57225, 247.18749)), ((407.5984, 238.48659), (424.19404, 244.30592), (418.80589, 249.69407), 135, '*D39', (422.35935, 231.82564))]:
    dim = msp.add_linear_dim(base=base, p1=p1, p2=p2, angle=angle, dimstyle='Standard$0', override={"dimdec": 2, "dimpost": '%%C<>mm'})
    dim.commit()
    dim.dimension.update_dxf_attribs({"geometry": picture, "text_midpoint": middle, "dimtype": 161})

# ---------------------------------------------------------------- leaders
for points in [[(458.54971, 288.6), (458.54971, 271.6)], [(408.99996, 288), (408.99996, 271)], [(421.49996, 288.51), (421.49996, 271.51)]]:
    msp.add_leader(points, dimstyle='Standard', override={"dimscale": 1, "dimasz": 2, "dimgap": 0.09, "dimtad": 0, "dimldrblk": 'ClosedBlank'})
msp.add_leader([(502.74996, 289.225), (502.74996, 260.98898)], dimstyle='Standard', override={"dimscale": 1, "dimasz": 2, "dimgap": 0.09, "dimtad": 0, "dimldrblk": 'ClosedBlank'}, dxfattribs=at)

doc.saveas('drawing.dxf')
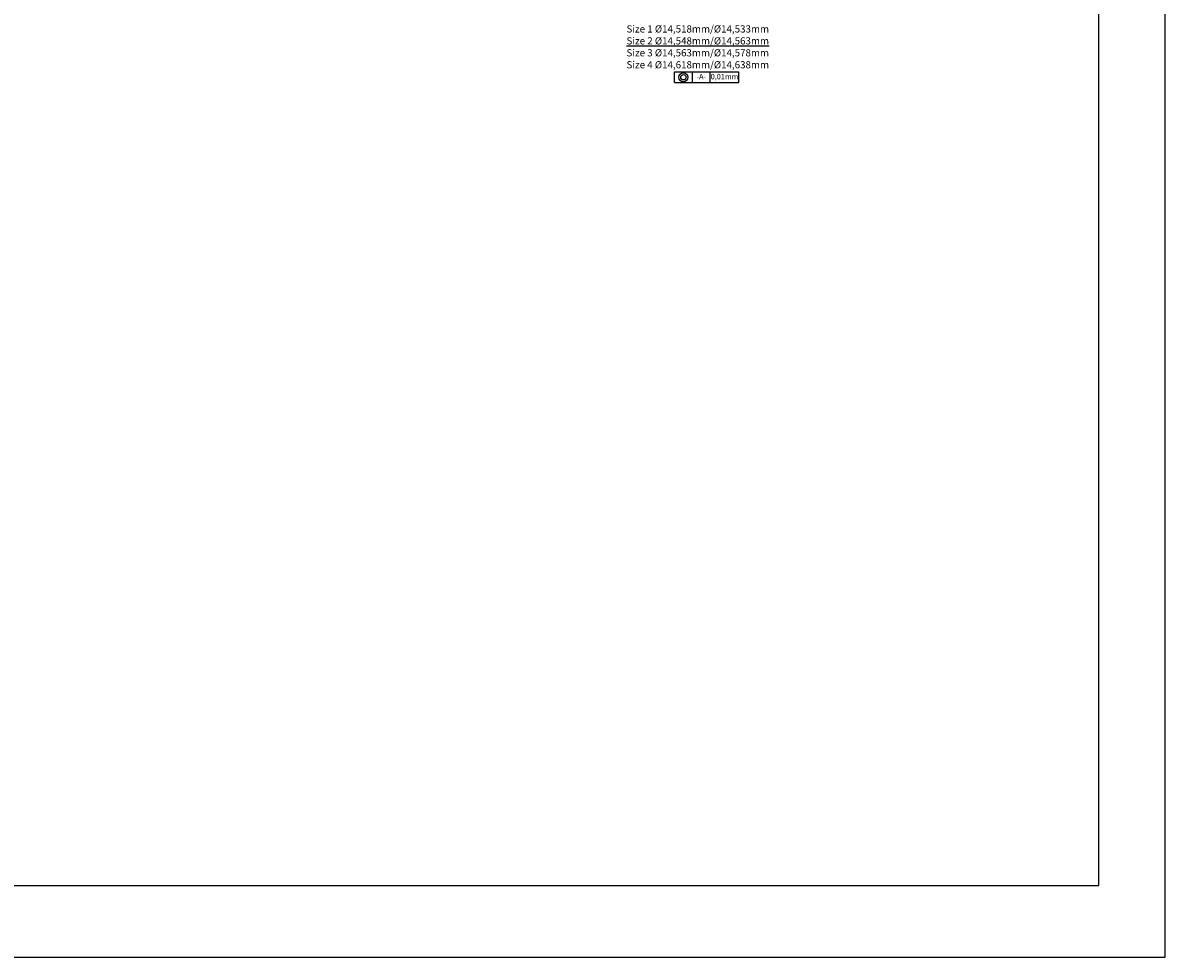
# Model space of a CAD drawing. Units: inches. Extents: x 0 to 841, y 0 to 594.
# Drawn here: x 522 to 841, y 0 to 261 of the extents above; entities that cross this region are included whole.
import ezdxf

# ---------------------------------------------------------------- set-up
doc = ezdxf.new("R2010")
doc.units = ezdxf.units.IN
doc.header["$MEASUREMENT"] = 0
doc.layers.add('TEXT', color=5, linetype='Continuous')

msp = doc.modelspace()

# ---------------------------------------------------------------- linework, layer by layer
for points in [[(-0.00004, 0), (840.99996, 0), (840.99996, 594), (-0.00004, 594)], [(18.49996, 20), (822.49996, 20), (822.49996, 574), (18.49996, 574)]]:
    msp.add_lwpolyline(points, close=True)
at = {"layer": 'TEXT', "color": 7}
for p, q in [((703.98457, 244.22497), (703.98457, 247.22497)), ((703.98457, 247.22497), (708.98457, 247.22497)), ((708.98457, 247.22497), (713.98457, 247.22497)), ((708.98457, 244.22497), (708.98457, 247.22497)), ((713.98457, 247.22497), (721.98457, 247.22497)), ((713.98457, 244.22497), (713.98457, 247.22497)), ((721.98457, 244.22497), (721.98457, 247.22497)), ((703.98457, 244.22497), (708.98457, 244.22497)), ((708.98457, 244.22497), (713.98457, 244.22497)), ((713.98457, 244.22497), (721.98457, 244.22497))]:
    msp.add_line(p, q, dxfattribs=at)
for radius in [1.25, 0.75]:
    msp.add_circle((706.48457, 245.72497), radius, dxfattribs=at)

# ---------------------------------------------------------------- texts
for s, insert, char_height, width, attachment_point in [('\\A1;Size 1 %%C14,518mm/%%C14,533mm\\P{\\LSize 2 %%C14,548mm/%%C14,563mm}\\PSize 3 %%C14,563mm/%%C14,578mm\\PSize 4 %%C14,618mm/%%C14,638mm', (690.59315, 260.22497), 2, 48.5376086, 1), ('-A-', (711.48457, 245.72497), 1.5, 1.19634, 5), ('0,01mm', (717.98457, 245.72497), 1.5, 6.6720954, 5)]:
    msp.add_mtext(s, dxfattribs=dict(at, insert=insert, char_height=char_height, width=width, attachment_point=attachment_point))

doc.saveas('drawing.dxf')
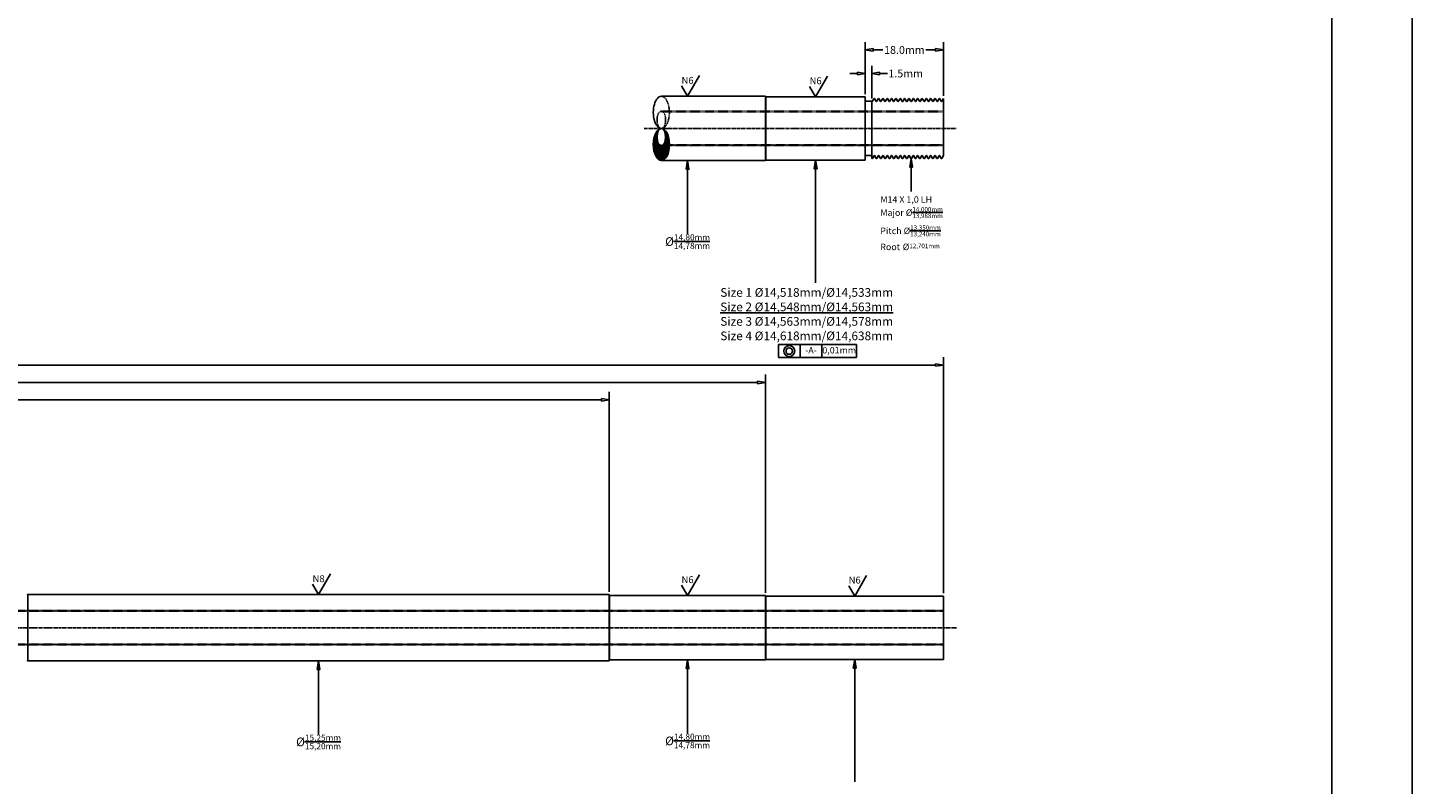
# Model space of a CAD drawing. Units: inches. Extents: x 0 to 841, y 0 to 594.
# Drawn here: x 522 to 841, y 261 to 435 of the extents above; entities that cross this region are included whole.
import ezdxf
from ezdxf.enums import TextEntityAlignment as Align

# ---------------------------------------------------------------- set-up
doc = ezdxf.new("R2010")
doc.units = ezdxf.units.IN
doc.header["$MEASUREMENT"] = 0
doc.linetypes.add('CENTER2', pattern=[1.125, 0.75, -0.125, 0.125, -0.125])
doc.linetypes.add('HIDDEN2', pattern=[0.1875, 0.125, -0.0625])
for name, color, linetype in [('CENTERLINE', 1, 'CENTER2'), ('HIDDEN', 5, 'HIDDEN2'), ('TEXT', 5, 'Continuous')]:
    doc.layers.add(name, color=color, linetype=linetype)
doc.dimstyles.get("Standard").update_dxf_attribs({"dimtxt": 0.18, "dimasz": 0.18, "dimexe": 0.18, "dimexo": 0.0625, "dimgap": 0.09, "dimtad": 0, "dimtih": 1, "dimtoh": 1, "dimdec": 4, "dimzin": 0, "dimdsep": 46, "dimtxsty": 'Standard', "dimcen": 0.09, "dimadec": 0, "dimazin": 0, "dimtfac": 1, "dimtdec": 4, "dimtofl": 0, "dimtmove": 0, "dimatfit": 3, "dimfxl": 0, "dimtolj": 1, "dimtzin": 0, "dimarcsym": 0})
doc.dimstyles.new('Standard$0', dxfattribs={"dimscale": 10, "dimtxt": 0.18, "dimasz": 0.18, "dimexe": 0.18, "dimexo": 0.0625, "dimgap": 0.09, "dimtad": 0, "dimtih": 1, "dimtoh": 1, "dimdec": 4, "dimzin": 4, "dimdsep": 46, "dimtxsty": 'Standard', "dimblk": 'CLOSEDBLANK', "dimcen": 0.09, "dimadec": 5, "dimazin": 1, "dimtfac": 1, "dimtdec": 4, "dimtofl": 0, "dimtmove": 0, "dimatfit": 3, "dimldrblk": 'CLOSEDBLANK', "dimfxl": 0, "dimtolj": 1, "dimtzin": 0, "dimarcsym": 0})

# ---------------------------------------------------------------- blocks, each defined once
blk = doc.blocks.new('_ClosedBlank')
at = {"color": 0, "linetype": 'ByBlock', "lineweight": -2}
for p, q in [((-1, 0.17), (0, 0)), ((-1, 0.17), (-1, -0.17)), ((0, 0), (-1, -0.17))]:
    blk.add_line(p, q, dxfattribs=at)
blk = doc.blocks.new('*D24')
at = {"color": 0, "lineweight": -2}
for p, q in [((108, 304.44), (108, 351.31)), ((656, 305.25), (656, 351.31)), ((109.8, 349.51), (375.85, 349.51)), ((654.2, 349.51), (388.15, 349.51))]:
    blk.add_line(p, q, dxfattribs=at)
at = {"layer": 'Defpoints', "color": 0}
for p in [(656, 349.51), (108, 303.81), (656, 304.62)]:
    blk.add_point(p, dxfattribs=at)
at = {"color": 0, "lineweight": -2, "xscale": 1.8, "yscale": 1.8, "zscale": 1.8, "rotation": 180}
blk.add_blockref('_ClosedBlank', (108, 349.51), dxfattribs=at)
at = {"color": 0, "lineweight": -2, "xscale": 1.8, "yscale": 1.8, "zscale": 1.8}
blk.add_blockref('_ClosedBlank', (656, 349.51), dxfattribs=at)
at = {"color": 0, "insert": (382, 349.51), "char_height": 1.8, "attachment_point": 5}
blk.add_mtext('\\A1;548.0mm', dxfattribs=at)
blk = doc.blocks.new('*D25')
at = {"color": 0, "lineweight": -2}
for p, q in [((108, 304.44), (108, 355.31)), ((692, 305), (692, 355.31)), ((109.8, 353.51), (393.85, 353.51)), ((690.2, 353.51), (406.15, 353.51))]:
    blk.add_line(p, q, dxfattribs=at)
at = {"layer": 'Defpoints', "color": 0}
for p in [(692, 353.51), (108, 303.81), (692, 304.37)]:
    blk.add_point(p, dxfattribs=at)
at = {"color": 0, "lineweight": -2, "xscale": 1.8, "yscale": 1.8, "zscale": 1.8, "rotation": 180}
blk.add_blockref('_ClosedBlank', (108, 353.51), dxfattribs=at)
at = {"color": 0, "lineweight": -2, "xscale": 1.8, "yscale": 1.8, "zscale": 1.8}
blk.add_blockref('_ClosedBlank', (692, 353.51), dxfattribs=at)
at = {"color": 0, "insert": (400, 353.51), "char_height": 1.8, "attachment_point": 5}
blk.add_mtext('\\A1;584.0mm', dxfattribs=at)
blk = doc.blocks.new('*D28')
at = {"color": 0, "lineweight": -2}
for p, q in [((108, 304.44), (108, 359.31)), ((109.8, 357.51), (414.35, 357.51)), ((731.2, 357.51), (426.65, 357.51)), ((733, 304.92), (733, 359.31))]:
    blk.add_line(p, q, dxfattribs=at)
at = {"layer": 'Defpoints', "color": 0}
for p in [(733, 357.51), (108, 303.81), (733, 304.3)]:
    blk.add_point(p, dxfattribs=at)
at = {"color": 0, "lineweight": -2, "xscale": 1.8, "yscale": 1.8, "zscale": 1.8, "rotation": 180}
blk.add_blockref('_ClosedBlank', (108, 357.51), dxfattribs=at)
at = {"color": 0, "lineweight": -2, "xscale": 1.8, "yscale": 1.8, "zscale": 1.8}
blk.add_blockref('_ClosedBlank', (733, 357.51), dxfattribs=at)
at = {"color": 0, "insert": (420.5, 357.51), "char_height": 1.8, "attachment_point": 5}
blk.add_mtext('\\A1;625.0mm', dxfattribs=at)
blk = doc.blocks.new('*D29')
at = {"color": 0, "lineweight": -2}
for p, q in [((715, 419.92), (715, 431.88)), ((733, 419.52), (733, 431.88)), ((716.8, 430.08), (719.05, 430.08)), ((731.2, 430.08), (728.95, 430.08))]:
    blk.add_line(p, q, dxfattribs=at)
at = {"layer": 'Defpoints', "color": 0}
for p in [(733, 430.08), (715, 419.3), (733, 418.89)]:
    blk.add_point(p, dxfattribs=at)
at = {"color": 0, "lineweight": -2, "xscale": 1.8, "yscale": 1.8, "zscale": 1.8, "rotation": 180}
blk.add_blockref('_ClosedBlank', (715, 430.08), dxfattribs=at)
at = {"color": 0, "lineweight": -2, "xscale": 1.8, "yscale": 1.8, "zscale": 1.8}
blk.add_blockref('_ClosedBlank', (733, 430.08), dxfattribs=at)
at = {"color": 0, "insert": (724, 430.08), "char_height": 1.8, "attachment_point": 5}
blk.add_mtext('\\A1;18.0mm', dxfattribs=at)
blk = doc.blocks.new('*D30')
at = {"color": 0, "lineweight": -2}
for p, q in [((713.2, 424.65), (711.4, 424.65)), ((715, 419.92), (715, 426.45)), ((716.5, 418.87), (716.5, 426.45)), ((718.3, 424.65), (720.1, 424.65))]:
    blk.add_line(p, q, dxfattribs=at)
at = {"layer": 'Defpoints', "color": 0}
for p in [(716.5, 424.65), (715, 419.3), (716.5, 418.25)]:
    blk.add_point(p, dxfattribs=at)
at = {"color": 0, "lineweight": -2, "xscale": 1.8, "yscale": 1.8, "zscale": 1.8}
blk.add_blockref('_ClosedBlank', (715, 424.65), dxfattribs=at)
at = {"color": 0, "lineweight": -2, "xscale": 1.8, "yscale": 1.8, "zscale": 1.8, "rotation": 180}
blk.add_blockref('_ClosedBlank', (716.5, 424.65), dxfattribs=at)
at = {"color": 0, "insert": (724.3, 424.65), "char_height": 1.8, "attachment_point": 5}
blk.add_mtext('\\A1;1.5mm', dxfattribs=at)

msp = doc.modelspace()

# ---------------------------------------------------------------- hatches: boundary and pattern name
h = msp.add_hatch()
h.set_pattern_fill('ANSI31', color=256, style=0)
h.set_pattern_definition([(45, (87.27502, 184.63051), (-0.088388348, 0.088388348), [])])
edge = h.paths.add_edge_path()
edge.add_ellipse((668.0169, 408.29993), major_axis=(0, 3.7), ratio=0.5, start_angle=0, end_angle=360, ccw=False)
edge = h.paths.add_edge_path(flags=16)
edge.add_ellipse((668.01684, 410.01875), major_axis=(0, 1.98118), ratio=0.5, start_angle=0, end_angle=360)

# ---------------------------------------------------------------- linework, layer by layer
for p, q in [((672.67515, 421.78125), (674.04996, 419.4)), ((674.04996, 419.4), (676.79959, 424.1625)), ((702.17515, 421.68125), (703.54996, 419.3)), ((703.54996, 419.3), (706.29959, 424.0625)), ((668.0169, 419.4), (691.99996, 419.4)), ((691.99996, 404.6), (691.99996, 419.4)), ((692.09996, 419.3), (714.99996, 419.3)), ((692.09996, 404.7), (692.09996, 419.3)), ((714.99996, 404.7), (714.99996, 419.3)), ((714.99996, 418.25), (716.49996, 418.25)), ((716.49996, 405.10825), (716.49996, 418.25)), ((716.49996, 418.24222), (716.5208, 418.20614)), ((716.49996, 418.24222), (716.5208, 418.20614)), ((716.5208, 418.20614), (716.60413, 418.20614)), ((716.60413, 418.20614), (716.5208, 418.20614)), ((716.60413, 418.20614), (716.99996, 418.89174)), ((716.99996, 418.89174), (717.12496, 418.89174)), ((717.12496, 418.89174), (717.5208, 418.20614)), ((717.49996, 418.24222), (717.5208, 418.20614)), ((717.5208, 418.20614), (717.60413, 418.20614)), ((717.60413, 418.20614), (717.5208, 418.20614)), ((717.60413, 418.20614), (717.99996, 418.89174)), ((717.99996, 418.89174), (718.12496, 418.89174)), ((718.12496, 418.89174), (718.5208, 418.20614)), ((718.49996, 418.24222), (718.5208, 418.20614)), ((718.5208, 418.20614), (718.60413, 418.20614)), ((718.60413, 418.20614), (718.5208, 418.20614)), ((718.60413, 418.20614), (718.99996, 418.89174)), ((718.99996, 418.89174), (719.12496, 418.89174)), ((719.12496, 418.89174), (719.5208, 418.20614)), ((719.49996, 418.24222), (719.5208, 418.20614)), ((719.5208, 418.20614), (719.60413, 418.20614)), ((719.60413, 418.20614), (719.5208, 418.20614)), ((719.60413, 418.20614), (719.99996, 418.89174)), ((719.99996, 418.89174), (720.12496, 418.89174)), ((720.12496, 418.89174), (720.5208, 418.20614)), ((720.49996, 418.24222), (720.5208, 418.20614)), ((720.5208, 418.20614), (720.60413, 418.20614)), ((720.60413, 418.20614), (720.5208, 418.20614)), ((720.60413, 418.20614), (720.99996, 418.89174)), ((720.99996, 418.89174), (721.12496, 418.89174)), ((721.12496, 418.89174), (721.5208, 418.20614)), ((721.5208, 418.20614), (721.60413, 418.20614)), ((721.60413, 418.20614), (721.5208, 418.20614)), ((721.60413, 418.20614), (721.99996, 418.89174)), ((721.99996, 418.89174), (722.12496, 418.89174)), ((722.12496, 418.89174), (722.5208, 418.20614)), ((722.60413, 418.20614), (722.5208, 418.20614)), ((722.60413, 418.20614), (722.99996, 418.89174)), ((722.99996, 418.89174), (723.12496, 418.89174)), ((723.12496, 418.89174), (723.5208, 418.20614)), ((723.60413, 418.20614), (723.5208, 418.20614)), ((723.60413, 418.20614), (723.99996, 418.89174)), ((723.99996, 418.89174), (724.12496, 418.89174)), ((724.12496, 418.89174), (724.5208, 418.20614)), ((724.60413, 418.20614), (724.5208, 418.20614)), ((724.60413, 418.20614), (724.99996, 418.89174)), ((724.99996, 418.89174), (725.12496, 418.89174)), ((725.12496, 418.89174), (725.5208, 418.20614)), ((725.60413, 418.20614), (725.5208, 418.20614)), ((725.60413, 418.20614), (725.99996, 418.89174)), ((725.99996, 418.89174), (726.12496, 418.89174)), ((726.12496, 418.89174), (726.5208, 418.20614)), ((726.60413, 418.20614), (726.5208, 418.20614)), ((726.60413, 418.20614), (726.99996, 418.89174)), ((726.99996, 418.89174), (727.12496, 418.89174)), ((727.12496, 418.89174), (727.5208, 418.20614)), ((727.60413, 418.20614), (727.5208, 418.20614)), ((727.60413, 418.20614), (727.99996, 418.89174)), ((727.99996, 418.89174), (728.12496, 418.89174)), ((728.12496, 418.89174), (728.5208, 418.20614)), ((728.60413, 418.20614), (728.5208, 418.20614)), ((728.60413, 418.20614), (728.99996, 418.89174)), ((728.99996, 418.89174), (729.12496, 418.89174)), ((729.12496, 418.89174), (729.5208, 418.20614)), ((729.60413, 418.20614), (729.5208, 418.20614)), ((729.60413, 418.20614), (729.99996, 418.89174)), ((729.99996, 418.89174), (730.12496, 418.89174)), ((730.12496, 418.89174), (730.5208, 418.20614)), ((730.60413, 418.20614), (730.5208, 418.20614)), ((730.60413, 418.20614), (730.99996, 418.89174)), ((730.99996, 418.89174), (731.12496, 418.89174)), ((731.12496, 418.89174), (731.5208, 418.20614)), ((731.60413, 418.20614), (731.5208, 418.20614)), ((731.60413, 418.20614), (731.99996, 418.89174)), ((731.99996, 418.89174), (732.12496, 418.89174)), ((732.12496, 418.89174), (732.5208, 418.20614)), ((732.60413, 418.20614), (732.5208, 418.20614)), ((732.60413, 418.20614), (732.99996, 418.89174)), ((732.99996, 418.89174), (732.99996, 405.75777)), ((714.99996, 405.75), (716.49996, 405.75)), ((716.49996, 405.10825), (716.62496, 405.10825)), ((716.62496, 405.10825), (717.0208, 405.79385)), ((717.0208, 405.79385), (717.10413, 405.79385)), ((717.10413, 405.79385), (717.0208, 405.79385)), ((717.10413, 405.79385), (717.49996, 405.10825)), ((717.49996, 405.10825), (717.62496, 405.10825)), ((717.62496, 405.10825), (718.0208, 405.79385)), ((718.0208, 405.79385), (718.10413, 405.79385)), ((718.10413, 405.79385), (718.0208, 405.79385)), ((718.10413, 405.79385), (718.49996, 405.10825)), ((718.49996, 405.10825), (718.62496, 405.10825)), ((718.62496, 405.10825), (719.0208, 405.79385)), ((719.0208, 405.79385), (719.10413, 405.79385)), ((719.10413, 405.79385), (719.0208, 405.79385)), ((719.10413, 405.79385), (719.49996, 405.10825)), ((719.49996, 405.10825), (719.62496, 405.10825)), ((719.62496, 405.10825), (720.0208, 405.79385)), ((720.0208, 405.79385), (720.10413, 405.79385)), ((720.10413, 405.79385), (720.0208, 405.79385)), ((720.10413, 405.79385), (720.49996, 405.10825)), ((720.49996, 405.10825), (720.62496, 405.10825)), ((720.62496, 405.10825), (721.0208, 405.79385)), ((721.0208, 405.79385), (721.10413, 405.79385)), ((721.10413, 405.79385), (721.0208, 405.79385)), ((721.10413, 405.79385), (721.49996, 405.10825)), ((721.49996, 405.10825), (721.62496, 405.10825)), ((721.62496, 405.10825), (722.0208, 405.79385)), ((722.10413, 405.79385), (722.0208, 405.79385)), ((722.10413, 405.79385), (722.49996, 405.10825)), ((722.49996, 405.10825), (722.62496, 405.10825)), ((722.62496, 405.10825), (723.0208, 405.79385)), ((723.10413, 405.79385), (723.0208, 405.79385)), ((723.10413, 405.79385), (723.49996, 405.10825)), ((723.49996, 405.10825), (723.62496, 405.10825)), ((723.62496, 405.10825), (724.0208, 405.79385)), ((724.10413, 405.79385), (724.0208, 405.79385)), ((724.10413, 405.79385), (724.49996, 405.10825)), ((724.49996, 405.10825), (724.62496, 405.10825)), ((724.62496, 405.10825), (725.0208, 405.79385)), ((725.10413, 405.79385), (725.0208, 405.79385)), ((725.10413, 405.79385), (725.49996, 405.10825)), ((725.49996, 405.10825), (725.62496, 405.10825)), ((725.62496, 405.10825), (726.0208, 405.79385)), ((726.10413, 405.79385), (726.0208, 405.79385)), ((726.10413, 405.79385), (726.49996, 405.10825)), ((726.49996, 405.10825), (726.62496, 405.10825)), ((726.62496, 405.10825), (727.0208, 405.79385)), ((727.10413, 405.79385), (727.0208, 405.79385)), ((727.10413, 405.79385), (727.49996, 405.10825)), ((727.49996, 405.10825), (727.62496, 405.10825)), ((727.62496, 405.10825), (728.0208, 405.79385)), ((728.10413, 405.79385), (728.0208, 405.79385)), ((728.10413, 405.79385), (728.49996, 405.10825)), ((728.49996, 405.10825), (728.62496, 405.10825)), ((728.62496, 405.10825), (729.0208, 405.79385)), ((729.10413, 405.79385), (729.0208, 405.79385)), ((729.10413, 405.79385), (729.49996, 405.10825)), ((729.49996, 405.10825), (729.62496, 405.10825)), ((729.62496, 405.10825), (730.0208, 405.79385)), ((730.10413, 405.79385), (730.0208, 405.79385)), ((730.10413, 405.79385), (730.49996, 405.10825)), ((730.49996, 405.10825), (730.62496, 405.10825)), ((730.62496, 405.10825), (731.0208, 405.79385)), ((731.10413, 405.79385), (731.0208, 405.79385)), ((731.10413, 405.79385), (731.49996, 405.10825)), ((731.49996, 405.10825), (731.62496, 405.10825)), ((731.62496, 405.10825), (732.0208, 405.79385)), ((732.10413, 405.79385), (732.0208, 405.79385)), ((732.10413, 405.79385), (732.49996, 405.10825)), ((732.49996, 405.10825), (732.62496, 405.10825)), ((732.62496, 405.10825), (732.99996, 405.75777)), ((668.0169, 404.6), (691.99996, 404.6)), ((692.09996, 404.7), (714.99996, 404.7)), ((589.04996, 304.625), (591.79959, 309.3875)), ((587.67515, 307.00625), (589.04996, 304.625)), ((672.67515, 306.78125), (674.04996, 304.4)), ((674.04996, 304.4), (676.79959, 309.1625)), ((711.17515, 306.68125), (712.54996, 304.3)), ((712.54996, 304.3), (715.29959, 309.0625)), ((522.09996, 304.625), (655.99996, 304.625)), ((522.09996, 289.375), (522.09996, 304.625)), ((655.99996, 289.375), (655.99996, 304.625)), ((656.09996, 304.4), (691.99996, 304.4)), ((656.09996, 289.6), (656.09996, 304.4)), ((691.99996, 289.6), (691.99996, 304.4)), ((692.09996, 304.3), (732.99996, 304.3)), ((692.09996, 289.7), (692.09996, 304.3)), ((732.99996, 289.7), (732.99996, 304.3)), ((522.09996, 289.375), (655.99996, 289.375)), ((656.09996, 289.6), (691.99996, 289.6)), ((692.09996, 289.7), (732.99996, 289.7))]:
    msp.add_line(p, q)
for points in [[(-0.00004, 0), (840.99996, 0), (840.99996, 594), (-0.00004, 594)], [(18.49996, 20), (822.49996, 20), (822.49996, 574), (18.49996, 574)]]:
    msp.add_lwpolyline(points, close=True)
for centre, start, end in [((692.09996, 419.4), 180, 270), ((692.09996, 404.6), 90, 180), ((522.09996, 304.725), 180, 270), ((656.09996, 304.5), 180, 270), ((692.09996, 304.4), 180, 270), ((522.09996, 289.275), 90, 180), ((656.09996, 289.5), 90, 180), ((692.09996, 289.6), 90, 180)]:
    msp.add_arc(centre, 0.1, start, end)
at = {"extrusion": (0, 0, -1)}
msp.add_ellipse((668.0169, 415.69993), major_axis=(0, -3.7), ratio=0.5, start_param=6.283185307, end_param=9.424777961, dxfattribs=at)
msp.add_ellipse((668.0169, 408.29993), major_axis=(0, 3.7), ratio=0.5, dxfattribs=at)
msp.add_ellipse((668.01684, 410.01875), major_axis=(0, 1.98118), ratio=0.5)
at = {"layer": 'CENTERLINE'}
for p, q in [((664.07369, 412), (735.99996, 412)), ((104.99996, 297), (735.99996, 297))]:
    msp.add_line(p, q, dxfattribs=at)
at = {"layer": 'HIDDEN'}
for p, q in [((668.0169, 415.9624), (732.99996, 415.9624)), ((668.0169, 415.81), (732.99996, 415.81)), ((668.0169, 408.0376), (732.99996, 408.0376)), ((668.39788, 408.19), (732.99996, 408.19)), ((162.42592, 300.9624), (732.99996, 300.9624)), ((162.57832, 300.81), (732.99996, 300.81)), ((162.42592, 293.0376), (732.99996, 293.0376)), ((162.57832, 293.19), (732.99996, 293.19))]:
    msp.add_line(p, q, dxfattribs=at)
at = {"layer": 'HIDDEN', "extrusion": (0, 0, -1)}
msp.add_ellipse((668.0167, 415.69993), major_axis=(0, -3.7), ratio=0.5, start_param=3.141592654, end_param=6.283185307, dxfattribs=at)
msp.add_ellipse((668.01684, 413.98111), major_axis=(0, -1.98118), ratio=0.5, dxfattribs=at)
at = {"layer": 'TEXT', "color": 7}
for p, q in [((694.98457, 359.22497), (694.98457, 362.22497)), ((694.98457, 362.22497), (699.98457, 362.22497)), ((699.98457, 362.22497), (704.98457, 362.22497)), ((699.98457, 359.22497), (699.98457, 362.22497)), ((704.98457, 362.22497), (712.98457, 362.22497)), ((704.98457, 359.22497), (704.98457, 362.22497)), ((712.98457, 359.22497), (712.98457, 362.22497)), ((694.98457, 359.22497), (699.98457, 359.22497)), ((699.98457, 359.22497), (704.98457, 359.22497)), ((704.98457, 359.22497), (712.98457, 359.22497))]:
    msp.add_line(p, q, dxfattribs=at)
for radius in [1.25, 0.75]:
    msp.add_circle((697.48457, 360.72497), radius, dxfattribs=at)

# ---------------------------------------------------------------- texts
for s, p in [('N6', (674.04996, 421.78125)), ('N6', (703.54996, 421.68125)), ('N8', (589.04996, 307.00625)), ('N6', (674.04996, 306.78125)), ('N6', (712.54996, 306.68125))]:
    msp.add_text(s, height=1.5875).set_placement(p, align=Align.BOTTOM_CENTER)
at = {"char_height": 2, "width": 10.5482646, "attachment_point": 2}
for s, insert in [('\\A1;%%C{\\H0.7x;\\S14,80mm/14,78mm;}', (674.04996, 387.625)), ('\\A1;%%C{\\H0.7x;\\S15,25mm/15,20mm;}', (589.04996, 272.375)), ('\\A1;%%C{\\H0.7x;\\S14,80mm/14,78mm;}', (674.04996, 272.6))]:
    msp.add_mtext(s, dxfattribs=dict(at, insert=insert))
at = {"layer": 'TEXT', "color": 7}
for s, insert, char_height, width, attachment_point in [('\\A1;{\\H0.75x;M14 X 1,0 LH\\PMajor %%C\\H0.7x;\\S14,000mm/13,988mm;\\H1.429x;\\PPitch %%C\\H0.7x;\\S13,350mm/13,240mm;\\H1.429x;\\PRoot} {\\H0.75x;%%C\\H0.7x;12,701mm}', (718.45201, 396.37091), 2, 19.3860592, 1), ('\\A1;Size 1 %%C14,518mm/%%C14,533mm\\P{\\LSize 2 %%C14,548mm/%%C14,563mm}\\PSize 3 %%C14,563mm/%%C14,578mm\\PSize 4 %%C14,618mm/%%C14,638mm', (681.59315, 375.22497), 2, 48.5376086, 1), ('-A-', (702.48457, 360.72497), 1.5, 1.19634, 5), ('0,01mm', (708.98457, 360.72497), 1.5, 6.6720954, 5)]:
    msp.add_mtext(s, dxfattribs=dict(at, insert=insert, char_height=char_height, width=width, attachment_point=attachment_point))

# ---------------------------------------------------------------- dimensions: what is measured, and where the dimension line sits
for base, p1, p2, picture, middle in [((732.99996, 430.07558), (714.99996, 419.3), (732.99996, 418.89174), '*D29', (723.99996, 430.07558)), ((732.99996, 357.51176), (107.99996, 303.815), (732.99996, 304.3), '*D28', (420.49996, 357.51176)), ((691.99996, 353.51323), (107.99996, 303.815), (691.99996, 304.375), '*D25', (399.99996, 353.51323)), ((655.99996, 349.51469), (107.99996, 303.815), (655.99996, 304.625), '*D24', (381.99996, 349.51469))]:
    dim = msp.add_linear_dim(base=base, p1=p1, p2=p2, dimstyle='Standard$0', override={"dimscale": 10, "dimdec": 1, "dimpost": 'mm', "dimblk1": 'ClosedBlank', "dimblk2": 'ClosedBlank', "dimsah": 1})
    dim.commit()
    dim.dimension.update_dxf_attribs({"geometry": picture, "text_midpoint": middle})
dim = msp.add_linear_dim(base=(716.49996, 424.65029), p1=(714.99996, 419.3), p2=(716.49996, 418.25), dimstyle='Standard$0', override={"dimscale": 10, "dimdec": 1, "dimpost": 'mm', "dimblk1": 'ClosedBlank', "dimblk2": 'ClosedBlank', "dimsah": 1})
dim.commit()
dim.dimension.update_dxf_attribs({"geometry": '*D30', "text_midpoint": (724.29996, 424.65029), "dimtype": 160})

# ---------------------------------------------------------------- leaders
for points in [[(725.56246, 405.10825), (725.56246, 397.45925)], [(674.04996, 404.6), (674.04996, 387.6)], [(589.04996, 289.375), (589.04996, 272.375)], [(674.04996, 289.6), (674.04996, 272.6)]]:
    msp.add_leader(points, dimstyle='Standard', override={"dimscale": 1, "dimasz": 2, "dimgap": 0.09, "dimtad": 0, "dimldrblk": 'ClosedBlank'})
for points in [[(703.54996, 404.7), (703.54996, 376.46398)], [(712.54996, 289.7), (712.54996, 261.46398)]]:
    msp.add_leader(points, dimstyle='Standard', override={"dimscale": 1, "dimasz": 2, "dimgap": 0.09, "dimtad": 0, "dimldrblk": 'ClosedBlank'}, dxfattribs=at)

doc.saveas('drawing.dxf')
